VERSION 5.8 ;
BUSBITCHARS "[]" ;
DIVIDERCHAR "/" ;
UNITS
    DATABASE MICRONS 1000 ;
END UNITS

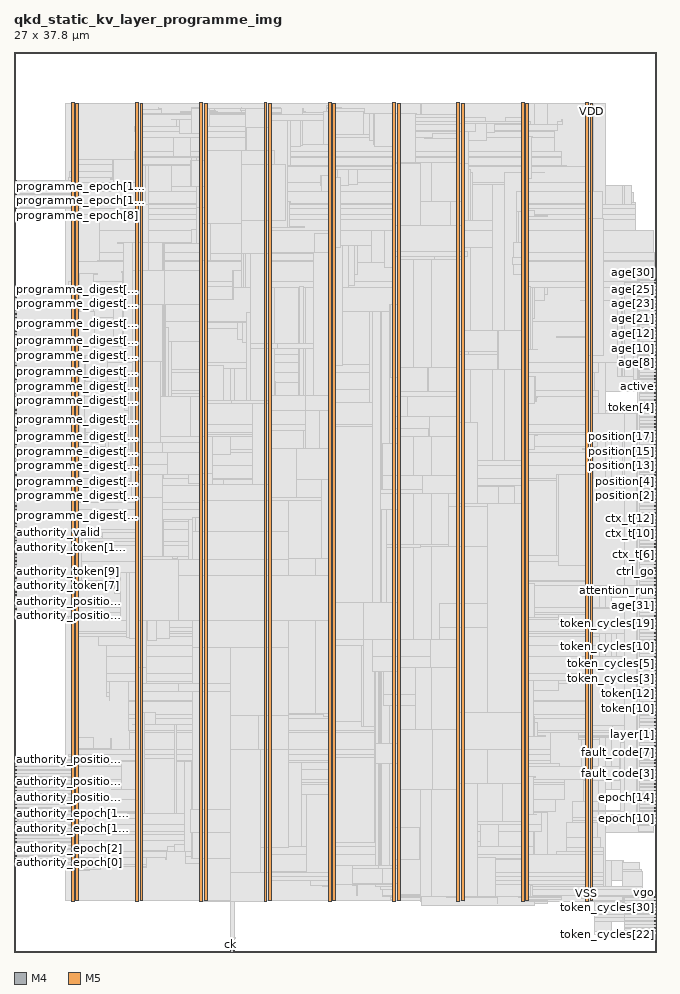
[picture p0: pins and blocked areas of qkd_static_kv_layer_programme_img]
MACRO qkd_static_kv_layer_programme_img
  FOREIGN qkd_static_kv_layer_programme_img 0 0 ;
  CLASS BLOCK ;
  SIZE 27 BY 37.8 ;
  PIN active
    DIRECTION OUTPUT ;
    USE SIGNAL ;
    PORT
      LAYER M4 ;
        RECT  26.916 23.76 27 23.784 ;
    END
  END active
  PIN age[0]
    DIRECTION OUTPUT ;
    USE SIGNAL ;
    PORT
      LAYER M4 ;
        RECT  26.916 23.904 27 23.928 ;
    END
  END age[0]
  PIN age[10]
    DIRECTION OUTPUT ;
    USE SIGNAL ;
    PORT
      LAYER M4 ;
        RECT  26.916 25.344 27 25.368 ;
    END
  END age[10]
  PIN age[11]
    DIRECTION OUTPUT ;
    USE SIGNAL ;
    PORT
      LAYER M4 ;
        RECT  26.916 25.488 27 25.512 ;
    END
  END age[11]
  PIN age[12]
    DIRECTION OUTPUT ;
    USE SIGNAL ;
    PORT
      LAYER M4 ;
        RECT  26.916 25.632 27 25.656 ;
    END
  END age[12]
  PIN age[13]
    DIRECTION OUTPUT ;
    USE SIGNAL ;
    PORT
      LAYER M4 ;
        RECT  26.916 25.776 27 25.8 ;
    END
  END age[13]
  PIN age[14]
    DIRECTION OUTPUT ;
    USE SIGNAL ;
    PORT
      LAYER M4 ;
        RECT  26.916 25.92 27 25.944 ;
    END
  END age[14]
  PIN age[15]
    DIRECTION OUTPUT ;
    USE SIGNAL ;
    PORT
      LAYER M4 ;
        RECT  26.916 26.064 27 26.088 ;
    END
  END age[15]
  PIN age[16]
    DIRECTION OUTPUT ;
    USE SIGNAL ;
    PORT
      LAYER M4 ;
        RECT  26.916 26.208 27 26.232 ;
    END
  END age[16]
  PIN age[17]
    DIRECTION OUTPUT ;
    USE SIGNAL ;
    PORT
      LAYER M4 ;
        RECT  26.916 26.352 27 26.376 ;
    END
  END age[17]
  PIN age[18]
    DIRECTION OUTPUT ;
    USE SIGNAL ;
    PORT
      LAYER M4 ;
        RECT  26.916 26.496 27 26.52 ;
    END
  END age[18]
  PIN age[19]
    DIRECTION OUTPUT ;
    USE SIGNAL ;
    PORT
      LAYER M4 ;
        RECT  26.916 26.64 27 26.664 ;
    END
  END age[19]
  PIN age[1]
    DIRECTION OUTPUT ;
    USE SIGNAL ;
    PORT
      LAYER M4 ;
        RECT  26.916 24.048 27 24.072 ;
    END
  END age[1]
  PIN age[20]
    DIRECTION OUTPUT ;
    USE SIGNAL ;
    PORT
      LAYER M4 ;
        RECT  26.916 26.784 27 26.808 ;
    END
  END age[20]
  PIN age[21]
    DIRECTION OUTPUT ;
    USE SIGNAL ;
    PORT
      LAYER M4 ;
        RECT  26.916 26.928 27 26.952 ;
    END
  END age[21]
  PIN age[22]
    DIRECTION OUTPUT ;
    USE SIGNAL ;
    PORT
      LAYER M4 ;
        RECT  26.916 27.072 27 27.096 ;
    END
  END age[22]
  PIN age[23]
    DIRECTION OUTPUT ;
    USE SIGNAL ;
    PORT
      LAYER M4 ;
        RECT  26.916 27.216 27 27.24 ;
    END
  END age[23]
  PIN age[24]
    DIRECTION OUTPUT ;
    USE SIGNAL ;
    PORT
      LAYER M4 ;
        RECT  26.916 27.36 27 27.384 ;
    END
  END age[24]
  PIN age[25]
    DIRECTION OUTPUT ;
    USE SIGNAL ;
    PORT
      LAYER M4 ;
        RECT  26.916 27.504 27 27.528 ;
    END
  END age[25]
  PIN age[26]
    DIRECTION OUTPUT ;
    USE SIGNAL ;
    PORT
      LAYER M4 ;
        RECT  26.916 27.648 27 27.672 ;
    END
  END age[26]
  PIN age[27]
    DIRECTION OUTPUT ;
    USE SIGNAL ;
    PORT
      LAYER M4 ;
        RECT  26.916 27.792 27 27.816 ;
    END
  END age[27]
  PIN age[28]
    DIRECTION OUTPUT ;
    USE SIGNAL ;
    PORT
      LAYER M4 ;
        RECT  26.916 27.936 27 27.96 ;
    END
  END age[28]
  PIN age[29]
    DIRECTION OUTPUT ;
    USE SIGNAL ;
    PORT
      LAYER M4 ;
        RECT  26.916 28.08 27 28.104 ;
    END
  END age[29]
  PIN age[2]
    DIRECTION OUTPUT ;
    USE SIGNAL ;
    PORT
      LAYER M4 ;
        RECT  26.916 24.192 27 24.216 ;
    END
  END age[2]
  PIN age[30]
    DIRECTION OUTPUT ;
    USE SIGNAL ;
    PORT
      LAYER M4 ;
        RECT  26.916 28.224 27 28.248 ;
    END
  END age[30]
  PIN age[31]
    DIRECTION OUTPUT ;
    USE SIGNAL ;
    PORT
      LAYER M4 ;
        RECT  26.916 14.544 27 14.568 ;
    END
  END age[31]
  PIN age[3]
    DIRECTION OUTPUT ;
    USE SIGNAL ;
    PORT
      LAYER M4 ;
        RECT  26.916 24.336 27 24.36 ;
    END
  END age[3]
  PIN age[4]
    DIRECTION OUTPUT ;
    USE SIGNAL ;
    PORT
      LAYER M4 ;
        RECT  26.916 24.48 27 24.504 ;
    END
  END age[4]
  PIN age[5]
    DIRECTION OUTPUT ;
    USE SIGNAL ;
    PORT
      LAYER M4 ;
        RECT  26.916 24.624 27 24.648 ;
    END
  END age[5]
  PIN age[6]
    DIRECTION OUTPUT ;
    USE SIGNAL ;
    PORT
      LAYER M4 ;
        RECT  26.916 24.768 27 24.792 ;
    END
  END age[6]
  PIN age[7]
    DIRECTION OUTPUT ;
    USE SIGNAL ;
    PORT
      LAYER M4 ;
        RECT  26.916 24.912 27 24.936 ;
    END
  END age[7]
  PIN age[8]
    DIRECTION OUTPUT ;
    USE SIGNAL ;
    PORT
      LAYER M4 ;
        RECT  26.916 25.056 27 25.08 ;
    END
  END age[8]
  PIN age[9]
    DIRECTION OUTPUT ;
    USE SIGNAL ;
    PORT
      LAYER M4 ;
        RECT  26.916 25.2 27 25.224 ;
    END
  END age[9]
  PIN attention_issue
    DIRECTION OUTPUT ;
    USE SIGNAL ;
    PORT
      LAYER M4 ;
        RECT  26.916 14.688 27 14.712 ;
    END
  END attention_issue
  PIN attention_run
    DIRECTION OUTPUT ;
    USE SIGNAL ;
    PORT
      LAYER M4 ;
        RECT  26.916 14.832 27 14.856 ;
    END
  END attention_run
  PIN authority_epoch[0]
    DIRECTION INPUT ;
    USE SIGNAL ;
    PORT
      LAYER M4 ;
        RECT  0 3.744 0.084 3.768 ;
    END
  END authority_epoch[0]
  PIN authority_epoch[10]
    DIRECTION INPUT ;
    USE SIGNAL ;
    PORT
      LAYER M4 ;
        RECT  0 5.184 0.084 5.208 ;
    END
  END authority_epoch[10]
  PIN authority_epoch[11]
    DIRECTION INPUT ;
    USE SIGNAL ;
    PORT
      LAYER M4 ;
        RECT  0 5.328 0.084 5.352 ;
    END
  END authority_epoch[11]
  PIN authority_epoch[12]
    DIRECTION INPUT ;
    USE SIGNAL ;
    PORT
      LAYER M4 ;
        RECT  0 5.472 0.084 5.496 ;
    END
  END authority_epoch[12]
  PIN authority_epoch[13]
    DIRECTION INPUT ;
    USE SIGNAL ;
    PORT
      LAYER M4 ;
        RECT  0 5.616 0.084 5.64 ;
    END
  END authority_epoch[13]
  PIN authority_epoch[14]
    DIRECTION INPUT ;
    USE SIGNAL ;
    PORT
      LAYER M4 ;
        RECT  0 5.76 0.084 5.784 ;
    END
  END authority_epoch[14]
  PIN authority_epoch[15]
    DIRECTION INPUT ;
    USE SIGNAL ;
    PORT
      LAYER M4 ;
        RECT  0 5.904 0.084 5.928 ;
    END
  END authority_epoch[15]
  PIN authority_epoch[1]
    DIRECTION INPUT ;
    USE SIGNAL ;
    PORT
      LAYER M4 ;
        RECT  0 3.888 0.084 3.912 ;
    END
  END authority_epoch[1]
  PIN authority_epoch[2]
    DIRECTION INPUT ;
    USE SIGNAL ;
    PORT
      LAYER M4 ;
        RECT  0 4.032 0.084 4.056 ;
    END
  END authority_epoch[2]
  PIN authority_epoch[3]
    DIRECTION INPUT ;
    USE SIGNAL ;
    PORT
      LAYER M4 ;
        RECT  0 4.176 0.084 4.2 ;
    END
  END authority_epoch[3]
  PIN authority_epoch[4]
    DIRECTION INPUT ;
    USE SIGNAL ;
    PORT
      LAYER M4 ;
        RECT  0 4.32 0.084 4.344 ;
    END
  END authority_epoch[4]
  PIN authority_epoch[5]
    DIRECTION INPUT ;
    USE SIGNAL ;
    PORT
      LAYER M4 ;
        RECT  0 4.464 0.084 4.488 ;
    END
  END authority_epoch[5]
  PIN authority_epoch[6]
    DIRECTION INPUT ;
    USE SIGNAL ;
    PORT
      LAYER M4 ;
        RECT  0 4.608 0.084 4.632 ;
    END
  END authority_epoch[6]
  PIN authority_epoch[7]
    DIRECTION INPUT ;
    USE SIGNAL ;
    PORT
      LAYER M4 ;
        RECT  0 4.752 0.084 4.776 ;
    END
  END authority_epoch[7]
  PIN authority_epoch[8]
    DIRECTION INPUT ;
    USE SIGNAL ;
    PORT
      LAYER M4 ;
        RECT  0 4.896 0.084 4.92 ;
    END
  END authority_epoch[8]
  PIN authority_epoch[9]
    DIRECTION INPUT ;
    USE SIGNAL ;
    PORT
      LAYER M4 ;
        RECT  0 5.04 0.084 5.064 ;
    END
  END authority_epoch[9]
  PIN authority_generation[0]
    DIRECTION INPUT ;
    USE SIGNAL ;
    PORT
      LAYER M4 ;
        RECT  0 6.048 0.084 6.072 ;
    END
  END authority_generation[0]
  PIN authority_generation[1]
    DIRECTION INPUT ;
    USE SIGNAL ;
    PORT
      LAYER M4 ;
        RECT  0 6.192 0.084 6.216 ;
    END
  END authority_generation[1]
  PIN authority_position[0]
    DIRECTION INPUT ;
    USE SIGNAL ;
    PORT
      LAYER M4 ;
        RECT  0 6.336 0.084 6.36 ;
    END
  END authority_position[0]
  PIN authority_position[10]
    DIRECTION INPUT ;
    USE SIGNAL ;
    PORT
      LAYER M4 ;
        RECT  0 7.776 0.084 7.8 ;
    END
  END authority_position[10]
  PIN authority_position[11]
    DIRECTION INPUT ;
    USE SIGNAL ;
    PORT
      LAYER M4 ;
        RECT  0 7.92 0.084 7.944 ;
    END
  END authority_position[11]
  PIN authority_position[12]
    DIRECTION INPUT ;
    USE SIGNAL ;
    PORT
      LAYER M4 ;
        RECT  0 8.064 0.084 8.088 ;
    END
  END authority_position[12]
  PIN authority_position[13]
    DIRECTION INPUT ;
    USE SIGNAL ;
    PORT
      LAYER M4 ;
        RECT  0 8.208 0.084 8.232 ;
    END
  END authority_position[13]
  PIN authority_position[14]
    DIRECTION INPUT ;
    USE SIGNAL ;
    PORT
      LAYER M4 ;
        RECT  0 14.112 0.084 14.136 ;
    END
  END authority_position[14]
  PIN authority_position[15]
    DIRECTION INPUT ;
    USE SIGNAL ;
    PORT
      LAYER M4 ;
        RECT  0 14.256 0.084 14.28 ;
    END
  END authority_position[15]
  PIN authority_position[16]
    DIRECTION INPUT ;
    USE SIGNAL ;
    PORT
      LAYER M4 ;
        RECT  0 14.4 0.084 14.424 ;
    END
  END authority_position[16]
  PIN authority_position[17]
    DIRECTION INPUT ;
    USE SIGNAL ;
    PORT
      LAYER M4 ;
        RECT  0 14.544 0.084 14.568 ;
    END
  END authority_position[17]
  PIN authority_position[1]
    DIRECTION INPUT ;
    USE SIGNAL ;
    PORT
      LAYER M4 ;
        RECT  0 6.48 0.084 6.504 ;
    END
  END authority_position[1]
  PIN authority_position[2]
    DIRECTION INPUT ;
    USE SIGNAL ;
    PORT
      LAYER M4 ;
        RECT  0 6.624 0.084 6.648 ;
    END
  END authority_position[2]
  PIN authority_position[3]
    DIRECTION INPUT ;
    USE SIGNAL ;
    PORT
      LAYER M4 ;
        RECT  0 6.768 0.084 6.792 ;
    END
  END authority_position[3]
  PIN authority_position[4]
    DIRECTION INPUT ;
    USE SIGNAL ;
    PORT
      LAYER M4 ;
        RECT  0 6.912 0.084 6.936 ;
    END
  END authority_position[4]
  PIN authority_position[5]
    DIRECTION INPUT ;
    USE SIGNAL ;
    PORT
      LAYER M4 ;
        RECT  0 7.056 0.084 7.08 ;
    END
  END authority_position[5]
  PIN authority_position[6]
    DIRECTION INPUT ;
    USE SIGNAL ;
    PORT
      LAYER M4 ;
        RECT  0 7.2 0.084 7.224 ;
    END
  END authority_position[6]
  PIN authority_position[7]
    DIRECTION INPUT ;
    USE SIGNAL ;
    PORT
      LAYER M4 ;
        RECT  0 7.344 0.084 7.368 ;
    END
  END authority_position[7]
  PIN authority_position[8]
    DIRECTION INPUT ;
    USE SIGNAL ;
    PORT
      LAYER M4 ;
        RECT  0 7.488 0.084 7.512 ;
    END
  END authority_position[8]
  PIN authority_position[9]
    DIRECTION INPUT ;
    USE SIGNAL ;
    PORT
      LAYER M4 ;
        RECT  0 7.632 0.084 7.656 ;
    END
  END authority_position[9]
  PIN authority_token[0]
    DIRECTION INPUT ;
    USE SIGNAL ;
    PORT
      LAYER M4 ;
        RECT  0 14.688 0.084 14.712 ;
    END
  END authority_token[0]
  PIN authority_token[10]
    DIRECTION INPUT ;
    USE SIGNAL ;
    PORT
      LAYER M4 ;
        RECT  0 16.128 0.084 16.152 ;
    END
  END authority_token[10]
  PIN authority_token[11]
    DIRECTION INPUT ;
    USE SIGNAL ;
    PORT
      LAYER M4 ;
        RECT  0 16.272 0.084 16.296 ;
    END
  END authority_token[11]
  PIN authority_token[12]
    DIRECTION INPUT ;
    USE SIGNAL ;
    PORT
      LAYER M4 ;
        RECT  0 16.416 0.084 16.44 ;
    END
  END authority_token[12]
  PIN authority_token[13]
    DIRECTION INPUT ;
    USE SIGNAL ;
    PORT
      LAYER M4 ;
        RECT  0 16.56 0.084 16.584 ;
    END
  END authority_token[13]
  PIN authority_token[14]
    DIRECTION INPUT ;
    USE SIGNAL ;
    PORT
      LAYER M4 ;
        RECT  0 16.704 0.084 16.728 ;
    END
  END authority_token[14]
  PIN authority_token[15]
    DIRECTION INPUT ;
    USE SIGNAL ;
    PORT
      LAYER M4 ;
        RECT  0 16.848 0.084 16.872 ;
    END
  END authority_token[15]
  PIN authority_token[16]
    DIRECTION INPUT ;
    USE SIGNAL ;
    PORT
      LAYER M4 ;
        RECT  0 16.992 0.084 17.016 ;
    END
  END authority_token[16]
  PIN authority_token[17]
    DIRECTION INPUT ;
    USE SIGNAL ;
    PORT
      LAYER M4 ;
        RECT  0 17.136 0.084 17.16 ;
    END
  END authority_token[17]
  PIN authority_token[1]
    DIRECTION INPUT ;
    USE SIGNAL ;
    PORT
      LAYER M4 ;
        RECT  0 14.832 0.084 14.856 ;
    END
  END authority_token[1]
  PIN authority_token[2]
    DIRECTION INPUT ;
    USE SIGNAL ;
    PORT
      LAYER M4 ;
        RECT  0 14.976 0.084 15 ;
    END
  END authority_token[2]
  PIN authority_token[3]
    DIRECTION INPUT ;
    USE SIGNAL ;
    PORT
      LAYER M4 ;
        RECT  0 15.12 0.084 15.144 ;
    END
  END authority_token[3]
  PIN authority_token[4]
    DIRECTION INPUT ;
    USE SIGNAL ;
    PORT
      LAYER M4 ;
        RECT  0 15.264 0.084 15.288 ;
    END
  END authority_token[4]
  PIN authority_token[5]
    DIRECTION INPUT ;
    USE SIGNAL ;
    PORT
      LAYER M4 ;
        RECT  0 15.408 0.084 15.432 ;
    END
  END authority_token[5]
  PIN authority_token[6]
    DIRECTION INPUT ;
    USE SIGNAL ;
    PORT
      LAYER M4 ;
        RECT  0 15.552 0.084 15.576 ;
    END
  END authority_token[6]
  PIN authority_token[7]
    DIRECTION INPUT ;
    USE SIGNAL ;
    PORT
      LAYER M4 ;
        RECT  0 15.696 0.084 15.72 ;
    END
  END authority_token[7]
  PIN authority_token[8]
    DIRECTION INPUT ;
    USE SIGNAL ;
    PORT
      LAYER M4 ;
        RECT  0 15.84 0.084 15.864 ;
    END
  END authority_token[8]
  PIN authority_token[9]
    DIRECTION INPUT ;
    USE SIGNAL ;
    PORT
      LAYER M4 ;
        RECT  0 15.984 0.084 16.008 ;
    END
  END authority_token[9]
  PIN authority_valid
    DIRECTION INPUT ;
    USE SIGNAL ;
    PORT
      LAYER M4 ;
        RECT  0 17.28 0.084 17.304 ;
    END
  END authority_valid
  PIN ck
    DIRECTION INPUT ;
    USE SIGNAL ;
    PORT
      LAYER M5 ;
        RECT  9.072 0 9.096 0.084 ;
    END
  END ck
  PIN completed_stage[0]
    DIRECTION OUTPUT ;
    USE SIGNAL ;
    PORT
      LAYER M4 ;
        RECT  26.916 14.976 27 15 ;
    END
  END completed_stage[0]
  PIN completed_stage[1]
    DIRECTION OUTPUT ;
    USE SIGNAL ;
    PORT
      LAYER M4 ;
        RECT  26.916 15.12 27 15.144 ;
    END
  END completed_stage[1]
  PIN completed_stage[2]
    DIRECTION OUTPUT ;
    USE SIGNAL ;
    PORT
      LAYER M4 ;
        RECT  26.916 15.264 27 15.288 ;
    END
  END completed_stage[2]
  PIN completed_stage[3]
    DIRECTION OUTPUT ;
    USE SIGNAL ;
    PORT
      LAYER M4 ;
        RECT  26.916 15.408 27 15.432 ;
    END
  END completed_stage[3]
  PIN completed_stage[4]
    DIRECTION OUTPUT ;
    USE SIGNAL ;
    PORT
      LAYER M4 ;
        RECT  26.916 15.552 27 15.576 ;
    END
  END completed_stage[4]
  PIN completed_stage[5]
    DIRECTION OUTPUT ;
    USE SIGNAL ;
    PORT
      LAYER M4 ;
        RECT  26.916 15.696 27 15.72 ;
    END
  END completed_stage[5]
  PIN configured
    DIRECTION OUTPUT ;
    USE SIGNAL ;
    PORT
      LAYER M4 ;
        RECT  26.916 15.84 27 15.864 ;
    END
  END configured
  PIN ctrl_go
    DIRECTION OUTPUT ;
    USE SIGNAL ;
    PORT
      LAYER M4 ;
        RECT  26.916 15.984 27 16.008 ;
    END
  END ctrl_go
  PIN ctx_t[0]
    DIRECTION OUTPUT ;
    USE SIGNAL ;
    PORT
      LAYER M4 ;
        RECT  26.916 16.128 27 16.152 ;
    END
  END ctx_t[0]
  PIN ctx_t[10]
    DIRECTION OUTPUT ;
    USE SIGNAL ;
    PORT
      LAYER M4 ;
        RECT  26.916 17.568 27 17.592 ;
    END
  END ctx_t[10]
  PIN ctx_t[11]
    DIRECTION OUTPUT ;
    USE SIGNAL ;
    PORT
      LAYER M4 ;
        RECT  26.916 17.712 27 17.736 ;
    END
  END ctx_t[11]
  PIN ctx_t[12]
    DIRECTION OUTPUT ;
    USE SIGNAL ;
    PORT
      LAYER M4 ;
        RECT  26.916 17.856 27 17.88 ;
    END
  END ctx_t[12]
  PIN ctx_t[13]
    DIRECTION OUTPUT ;
    USE SIGNAL ;
    PORT
      LAYER M4 ;
        RECT  26.916 18 27 18.024 ;
    END
  END ctx_t[13]
  PIN ctx_t[1]
    DIRECTION OUTPUT ;
    USE SIGNAL ;
    PORT
      LAYER M4 ;
        RECT  26.916 16.272 27 16.296 ;
    END
  END ctx_t[1]
  PIN ctx_t[2]
    DIRECTION OUTPUT ;
    USE SIGNAL ;
    PORT
      LAYER M4 ;
        RECT  26.916 16.416 27 16.44 ;
    END
  END ctx_t[2]
  PIN ctx_t[3]
    DIRECTION OUTPUT ;
    USE SIGNAL ;
    PORT
      LAYER M4 ;
        RECT  26.916 16.56 27 16.584 ;
    END
  END ctx_t[3]
  PIN ctx_t[4]
    DIRECTION OUTPUT ;
    USE SIGNAL ;
    PORT
      LAYER M4 ;
        RECT  26.916 16.704 27 16.728 ;
    END
  END ctx_t[4]
  PIN ctx_t[5]
    DIRECTION OUTPUT ;
    USE SIGNAL ;
    PORT
      LAYER M4 ;
        RECT  26.916 16.848 27 16.872 ;
    END
  END ctx_t[5]
  PIN ctx_t[6]
    DIRECTION OUTPUT ;
    USE SIGNAL ;
    PORT
      LAYER M4 ;
        RECT  26.916 16.992 27 17.016 ;
    END
  END ctx_t[6]
  PIN ctx_t[7]
    DIRECTION OUTPUT ;
    USE SIGNAL ;
    PORT
      LAYER M4 ;
        RECT  26.916 17.136 27 17.16 ;
    END
  END ctx_t[7]
  PIN ctx_t[8]
    DIRECTION OUTPUT ;
    USE SIGNAL ;
    PORT
      LAYER M4 ;
        RECT  26.916 17.28 27 17.304 ;
    END
  END ctx_t[8]
  PIN ctx_t[9]
    DIRECTION OUTPUT ;
    USE SIGNAL ;
    PORT
      LAYER M4 ;
        RECT  26.916 17.424 27 17.448 ;
    END
  END ctx_t[9]
  PIN done
    DIRECTION OUTPUT ;
    USE SIGNAL ;
    PORT
      LAYER M4 ;
        RECT  26.916 18.144 27 18.168 ;
    END
  END done
  PIN epoch[0]
    DIRECTION OUTPUT ;
    USE SIGNAL ;
    PORT
      LAYER M4 ;
        RECT  26.916 18.288 27 18.312 ;
    END
  END epoch[0]
  PIN epoch[10]
    DIRECTION OUTPUT ;
    USE SIGNAL ;
    PORT
      LAYER M4 ;
        RECT  26.916 5.904 27 5.928 ;
    END
  END epoch[10]
  PIN epoch[11]
    DIRECTION OUTPUT ;
    USE SIGNAL ;
    PORT
      LAYER M4 ;
        RECT  26.916 6.048 27 6.072 ;
    END
  END epoch[11]
  PIN epoch[12]
    DIRECTION OUTPUT ;
    USE SIGNAL ;
    PORT
      LAYER M4 ;
        RECT  26.916 6.192 27 6.216 ;
    END
  END epoch[12]
  PIN epoch[13]
    DIRECTION OUTPUT ;
    USE SIGNAL ;
    PORT
      LAYER M4 ;
        RECT  26.916 6.336 27 6.36 ;
    END
  END epoch[13]
  PIN epoch[14]
    DIRECTION OUTPUT ;
    USE SIGNAL ;
    PORT
      LAYER M4 ;
        RECT  26.916 6.48 27 6.504 ;
    END
  END epoch[14]
  PIN epoch[15]
    DIRECTION OUTPUT ;
    USE SIGNAL ;
    PORT
      LAYER M4 ;
        RECT  26.916 6.624 27 6.648 ;
    END
  END epoch[15]
  PIN epoch[1]
    DIRECTION OUTPUT ;
    USE SIGNAL ;
    PORT
      LAYER M4 ;
        RECT  26.916 18.432 27 18.456 ;
    END
  END epoch[1]
  PIN epoch[2]
    DIRECTION OUTPUT ;
    USE SIGNAL ;
    PORT
      LAYER M4 ;
        RECT  26.916 18.576 27 18.6 ;
    END
  END epoch[2]
  PIN epoch[3]
    DIRECTION OUTPUT ;
    USE SIGNAL ;
    PORT
      LAYER M4 ;
        RECT  26.916 18.72 27 18.744 ;
    END
  END epoch[3]
  PIN epoch[4]
    DIRECTION OUTPUT ;
    USE SIGNAL ;
    PORT
      LAYER M4 ;
        RECT  26.916 18.864 27 18.888 ;
    END
  END epoch[4]
  PIN epoch[5]
    DIRECTION OUTPUT ;
    USE SIGNAL ;
    PORT
      LAYER M4 ;
        RECT  26.916 19.008 27 19.032 ;
    END
  END epoch[5]
  PIN epoch[6]
    DIRECTION OUTPUT ;
    USE SIGNAL ;
    PORT
      LAYER M4 ;
        RECT  26.916 5.328 27 5.352 ;
    END
  END epoch[6]
  PIN epoch[7]
    DIRECTION OUTPUT ;
    USE SIGNAL ;
    PORT
      LAYER M4 ;
        RECT  26.916 5.472 27 5.496 ;
    END
  END epoch[7]
  PIN epoch[8]
    DIRECTION OUTPUT ;
    USE SIGNAL ;
    PORT
      LAYER M4 ;
        RECT  26.916 5.616 27 5.64 ;
    END
  END epoch[8]
  PIN epoch[9]
    DIRECTION OUTPUT ;
    USE SIGNAL ;
    PORT
      LAYER M4 ;
        RECT  26.916 5.76 27 5.784 ;
    END
  END epoch[9]
  PIN expected_upstream_quiet
    DIRECTION OUTPUT ;
    USE SIGNAL ;
    PORT
      LAYER M4 ;
        RECT  26.916 6.768 27 6.792 ;
    END
  END expected_upstream_quiet
  PIN fault
    DIRECTION OUTPUT ;
    USE SIGNAL ;
    PORT
      LAYER M4 ;
        RECT  26.916 6.912 27 6.936 ;
    END
  END fault
  PIN fault_code[0]
    DIRECTION OUTPUT ;
    USE SIGNAL ;
    PORT
      LAYER M4 ;
        RECT  26.916 7.056 27 7.08 ;
    END
  END fault_code[0]
  PIN fault_code[1]
    DIRECTION OUTPUT ;
    USE SIGNAL ;
    PORT
      LAYER M4 ;
        RECT  26.916 7.2 27 7.224 ;
    END
  END fault_code[1]
  PIN fault_code[2]
    DIRECTION OUTPUT ;
    USE SIGNAL ;
    PORT
      LAYER M4 ;
        RECT  26.916 7.344 27 7.368 ;
    END
  END fault_code[2]
  PIN fault_code[3]
    DIRECTION OUTPUT ;
    USE SIGNAL ;
    PORT
      LAYER M4 ;
        RECT  26.916 7.488 27 7.512 ;
    END
  END fault_code[3]
  PIN fault_code[4]
    DIRECTION OUTPUT ;
    USE SIGNAL ;
    PORT
      LAYER M4 ;
        RECT  26.916 7.632 27 7.656 ;
    END
  END fault_code[4]
  PIN fault_code[5]
    DIRECTION OUTPUT ;
    USE SIGNAL ;
    PORT
      LAYER M4 ;
        RECT  26.916 7.776 27 7.8 ;
    END
  END fault_code[5]
  PIN fault_code[6]
    DIRECTION OUTPUT ;
    USE SIGNAL ;
    PORT
      LAYER M4 ;
        RECT  26.916 7.92 27 7.944 ;
    END
  END fault_code[6]
  PIN fault_code[7]
    DIRECTION OUTPUT ;
    USE SIGNAL ;
    PORT
      LAYER M4 ;
        RECT  26.916 8.064 27 8.088 ;
    END
  END fault_code[7]
  PIN generation[0]
    DIRECTION OUTPUT ;
    USE SIGNAL ;
    PORT
      LAYER M4 ;
        RECT  26.916 8.208 27 8.232 ;
    END
  END generation[0]
  PIN generation[1]
    DIRECTION OUTPUT ;
    USE SIGNAL ;
    PORT
      LAYER M4 ;
        RECT  26.916 8.352 27 8.376 ;
    END
  END generation[1]
  PIN kgo
    DIRECTION OUTPUT ;
    USE SIGNAL ;
    PORT
      LAYER M4 ;
        RECT  26.916 8.496 27 8.52 ;
    END
  END kgo
  PIN layer[0]
    DIRECTION OUTPUT ;
    USE SIGNAL ;
    PORT
      LAYER M4 ;
        RECT  26.916 8.64 27 8.664 ;
    END
  END layer[0]
  PIN layer[1]
    DIRECTION OUTPUT ;
    USE SIGNAL ;
    PORT
      LAYER M4 ;
        RECT  26.916 8.784 27 8.808 ;
    END
  END layer[1]
  PIN layer[2]
    DIRECTION OUTPUT ;
    USE SIGNAL ;
    PORT
      LAYER M4 ;
        RECT  26.916 8.928 27 8.952 ;
    END
  END layer[2]
  PIN layer[3]
    DIRECTION OUTPUT ;
    USE SIGNAL ;
    PORT
      LAYER M4 ;
        RECT  26.916 9.072 27 9.096 ;
    END
  END layer[3]
  PIN layer[4]
    DIRECTION OUTPUT ;
    USE SIGNAL ;
    PORT
      LAYER M4 ;
        RECT  26.916 9.216 27 9.24 ;
    END
  END layer[4]
  PIN layer[5]
    DIRECTION OUTPUT ;
    USE SIGNAL ;
    PORT
      LAYER M4 ;
        RECT  26.916 9.36 27 9.384 ;
    END
  END layer[5]
  PIN link_start
    DIRECTION OUTPUT ;
    USE SIGNAL ;
    PORT
      LAYER M4 ;
        RECT  26.916 9.504 27 9.528 ;
    END
  END link_start
  PIN position[0]
    DIRECTION OUTPUT ;
    USE SIGNAL ;
    PORT
      LAYER M4 ;
        RECT  26.916 9.648 27 9.672 ;
    END
  END position[0]
  PIN position[10]
    DIRECTION OUTPUT ;
    USE SIGNAL ;
    PORT
      LAYER M4 ;
        RECT  26.916 20.304 27 20.328 ;
    END
  END position[10]
  PIN position[11]
    DIRECTION OUTPUT ;
    USE SIGNAL ;
    PORT
      LAYER M4 ;
        RECT  26.916 20.448 27 20.472 ;
    END
  END position[11]
  PIN position[12]
    DIRECTION OUTPUT ;
    USE SIGNAL ;
    PORT
      LAYER M4 ;
        RECT  26.916 20.592 27 20.616 ;
    END
  END position[12]
  PIN position[13]
    DIRECTION OUTPUT ;
    USE SIGNAL ;
    PORT
      LAYER M4 ;
        RECT  26.916 20.736 27 20.76 ;
    END
  END position[13]
  PIN position[14]
    DIRECTION OUTPUT ;
    USE SIGNAL ;
    PORT
      LAYER M4 ;
        RECT  26.916 20.88 27 20.904 ;
    END
  END position[14]
  PIN position[15]
    DIRECTION OUTPUT ;
    USE SIGNAL ;
    PORT
      LAYER M4 ;
        RECT  26.916 21.024 27 21.048 ;
    END
  END position[15]
  PIN position[16]
    DIRECTION OUTPUT ;
    USE SIGNAL ;
    PORT
      LAYER M4 ;
        RECT  26.916 21.168 27 21.192 ;
    END
  END position[16]
  PIN position[17]
    DIRECTION OUTPUT ;
    USE SIGNAL ;
    PORT
      LAYER M4 ;
        RECT  26.916 21.312 27 21.336 ;
    END
  END position[17]
  PIN position[1]
    DIRECTION OUTPUT ;
    USE SIGNAL ;
    PORT
      LAYER M4 ;
        RECT  26.916 9.792 27 9.816 ;
    END
  END position[1]
  PIN position[2]
    DIRECTION OUTPUT ;
    USE SIGNAL ;
    PORT
      LAYER M4 ;
        RECT  26.916 19.152 27 19.176 ;
    END
  END position[2]
  PIN position[3]
    DIRECTION OUTPUT ;
    USE SIGNAL ;
    PORT
      LAYER M4 ;
        RECT  26.916 19.296 27 19.32 ;
    END
  END position[3]
  PIN position[4]
    DIRECTION OUTPUT ;
    USE SIGNAL ;
    PORT
      LAYER M4 ;
        RECT  26.916 19.44 27 19.464 ;
    END
  END position[4]
  PIN position[5]
    DIRECTION OUTPUT ;
    USE SIGNAL ;
    PORT
      LAYER M4 ;
        RECT  26.916 19.584 27 19.608 ;
    END
  END position[5]
  PIN position[6]
    DIRECTION OUTPUT ;
    USE SIGNAL ;
    PORT
      LAYER M4 ;
        RECT  26.916 19.728 27 19.752 ;
    END
  END position[6]
  PIN position[7]
    DIRECTION OUTPUT ;
    USE SIGNAL ;
    PORT
      LAYER M4 ;
        RECT  26.916 19.872 27 19.896 ;
    END
  END position[7]
  PIN position[8]
    DIRECTION OUTPUT ;
    USE SIGNAL ;
    PORT
      LAYER M4 ;
        RECT  26.916 20.016 27 20.04 ;
    END
  END position[8]
  PIN position[9]
    DIRECTION OUTPUT ;
    USE SIGNAL ;
    PORT
      LAYER M4 ;
        RECT  26.916 20.16 27 20.184 ;
    END
  END position[9]
  PIN programme_authorized
    DIRECTION INPUT ;
    USE SIGNAL ;
    PORT
      LAYER M4 ;
        RECT  0 17.424 0.084 17.448 ;
    END
  END programme_authorized
  PIN programme_digest[0]
    DIRECTION INPUT ;
    USE SIGNAL ;
    PORT
      LAYER M4 ;
        RECT  0 17.568 0.084 17.592 ;
    END
  END programme_digest[0]
  PIN programme_digest[10]
    DIRECTION INPUT ;
    USE SIGNAL ;
    PORT
      LAYER M4 ;
        RECT  0 23.616 0.084 23.64 ;
    END
  END programme_digest[10]
  PIN programme_digest[11]
    DIRECTION INPUT ;
    USE SIGNAL ;
    PORT
      LAYER M4 ;
        RECT  0 23.76 0.084 23.784 ;
    END
  END programme_digest[11]
  PIN programme_digest[12]
    DIRECTION INPUT ;
    USE SIGNAL ;
    PORT
      LAYER M4 ;
        RECT  0 23.904 0.084 23.928 ;
    END
  END programme_digest[12]
  PIN programme_digest[13]
    DIRECTION INPUT ;
    USE SIGNAL ;
    PORT
      LAYER M4 ;
        RECT  0 24.048 0.084 24.072 ;
    END
  END programme_digest[13]
  PIN programme_digest[14]
    DIRECTION INPUT ;
    USE SIGNAL ;
    PORT
      LAYER M4 ;
        RECT  0 24.192 0.084 24.216 ;
    END
  END programme_digest[14]
  PIN programme_digest[15]
    DIRECTION INPUT ;
    USE SIGNAL ;
    PORT
      LAYER M4 ;
        RECT  0 24.336 0.084 24.36 ;
    END
  END programme_digest[15]
  PIN programme_digest[16]
    DIRECTION INPUT ;
    USE SIGNAL ;
    PORT
      LAYER M4 ;
        RECT  0 24.48 0.084 24.504 ;
    END
  END programme_digest[16]
  PIN programme_digest[17]
    DIRECTION INPUT ;
    USE SIGNAL ;
    PORT
      LAYER M4 ;
        RECT  0 24.624 0.084 24.648 ;
    END
  END programme_digest[17]
  PIN programme_digest[18]
    DIRECTION INPUT ;
    USE SIGNAL ;
    PORT
      LAYER M4 ;
        RECT  0 24.768 0.084 24.792 ;
    END
  END programme_digest[18]
  PIN programme_digest[19]
    DIRECTION INPUT ;
    USE SIGNAL ;
    PORT
      LAYER M4 ;
        RECT  0 24.912 0.084 24.936 ;
    END
  END programme_digest[19]
  PIN programme_digest[1]
    DIRECTION INPUT ;
    USE SIGNAL ;
    PORT
      LAYER M4 ;
        RECT  0 17.712 0.084 17.736 ;
    END
  END programme_digest[1]
  PIN programme_digest[20]
    DIRECTION INPUT ;
    USE SIGNAL ;
    PORT
      LAYER M4 ;
        RECT  0 25.056 0.084 25.08 ;
    END
  END programme_digest[20]
  PIN programme_digest[21]
    DIRECTION INPUT ;
    USE SIGNAL ;
    PORT
      LAYER M4 ;
        RECT  0 25.2 0.084 25.224 ;
    END
  END programme_digest[21]
  PIN programme_digest[22]
    DIRECTION INPUT ;
    USE SIGNAL ;
    PORT
      LAYER M4 ;
        RECT  0 25.344 0.084 25.368 ;
    END
  END programme_digest[22]
  PIN programme_digest[23]
    DIRECTION INPUT ;
    USE SIGNAL ;
    PORT
      LAYER M4 ;
        RECT  0 25.488 0.084 25.512 ;
    END
  END programme_digest[23]
  PIN programme_digest[24]
    DIRECTION INPUT ;
    USE SIGNAL ;
    PORT
      LAYER M4 ;
        RECT  0 25.632 0.084 25.656 ;
    END
  END programme_digest[24]
  PIN programme_digest[25]
    DIRECTION INPUT ;
    USE SIGNAL ;
    PORT
      LAYER M4 ;
        RECT  0 25.776 0.084 25.8 ;
    END
  END programme_digest[25]
  PIN programme_digest[26]
    DIRECTION INPUT ;
    USE SIGNAL ;
    PORT
      LAYER M4 ;
        RECT  0 25.92 0.084 25.944 ;
    END
  END programme_digest[26]
  PIN programme_digest[27]
    DIRECTION INPUT ;
    USE SIGNAL ;
    PORT
      LAYER M4 ;
        RECT  0 26.064 0.084 26.088 ;
    END
  END programme_digest[27]
  PIN programme_digest[28]
    DIRECTION INPUT ;
    USE SIGNAL ;
    PORT
      LAYER M4 ;
        RECT  0 26.208 0.084 26.232 ;
    END
  END programme_digest[28]
  PIN programme_digest[29]
    DIRECTION INPUT ;
    USE SIGNAL ;
    PORT
      LAYER M4 ;
        RECT  0 26.352 0.084 26.376 ;
    END
  END programme_digest[29]
  PIN programme_digest[2]
    DIRECTION INPUT ;
    USE SIGNAL ;
    PORT
      LAYER M4 ;
        RECT  0 17.856 0.084 17.88 ;
    END
  END programme_digest[2]
  PIN programme_digest[30]
    DIRECTION INPUT ;
    USE SIGNAL ;
    PORT
      LAYER M4 ;
        RECT  0 26.496 0.084 26.52 ;
    END
  END programme_digest[30]
  PIN programme_digest[31]
    DIRECTION INPUT ;
    USE SIGNAL ;
    PORT
      LAYER M4 ;
        RECT  0 26.64 0.084 26.664 ;
    END
  END programme_digest[31]
  PIN programme_digest[32]
    DIRECTION INPUT ;
    USE SIGNAL ;
    PORT
      LAYER M4 ;
        RECT  0 26.784 0.084 26.808 ;
    END
  END programme_digest[32]
  PIN programme_digest[33]
    DIRECTION INPUT ;
    USE SIGNAL ;
    PORT
      LAYER M4 ;
        RECT  0 26.928 0.084 26.952 ;
    END
  END programme_digest[33]
  PIN programme_digest[34]
    DIRECTION INPUT ;
    USE SIGNAL ;
    PORT
      LAYER M4 ;
        RECT  0 27.072 0.084 27.096 ;
    END
  END programme_digest[34]
  PIN programme_digest[35]
    DIRECTION INPUT ;
    USE SIGNAL ;
    PORT
      LAYER M4 ;
        RECT  0 27.216 0.084 27.24 ;
    END
  END programme_digest[35]
  PIN programme_digest[36]
    DIRECTION INPUT ;
    USE SIGNAL ;
    PORT
      LAYER M4 ;
        RECT  0 27.36 0.084 27.384 ;
    END
  END programme_digest[36]
  PIN programme_digest[37]
    DIRECTION INPUT ;
    USE SIGNAL ;
    PORT
      LAYER M4 ;
        RECT  0 27.504 0.084 27.528 ;
    END
  END programme_digest[37]
  PIN programme_digest[38]
    DIRECTION INPUT ;
    USE SIGNAL ;
    PORT
      LAYER M4 ;
        RECT  0 27.648 0.084 27.672 ;
    END
  END programme_digest[38]
  PIN programme_digest[39]
    DIRECTION INPUT ;
    USE SIGNAL ;
    PORT
      LAYER M4 ;
        RECT  0 27.792 0.084 27.816 ;
    END
  END programme_digest[39]
  PIN programme_digest[3]
    DIRECTION INPUT ;
    USE SIGNAL ;
    PORT
      LAYER M4 ;
        RECT  0 18 0.084 18.024 ;
    END
  END programme_digest[3]
  PIN programme_digest[40]
    DIRECTION INPUT ;
    USE SIGNAL ;
    PORT
      LAYER M4 ;
        RECT  0 18.72 0.084 18.744 ;
    END
  END programme_digest[40]
  PIN programme_digest[41]
    DIRECTION INPUT ;
    USE SIGNAL ;
    PORT
      LAYER M4 ;
        RECT  0 18.864 0.084 18.888 ;
    END
  END programme_digest[41]
  PIN programme_digest[42]
    DIRECTION INPUT ;
    USE SIGNAL ;
    PORT
      LAYER M4 ;
        RECT  0 19.008 0.084 19.032 ;
    END
  END programme_digest[42]
  PIN programme_digest[43]
    DIRECTION INPUT ;
    USE SIGNAL ;
    PORT
      LAYER M4 ;
        RECT  0 19.152 0.084 19.176 ;
    END
  END programme_digest[43]
  PIN programme_digest[44]
    DIRECTION INPUT ;
    USE SIGNAL ;
    PORT
      LAYER M4 ;
        RECT  0 19.296 0.084 19.32 ;
    END
  END programme_digest[44]
  PIN programme_digest[45]
    DIRECTION INPUT ;
    USE SIGNAL ;
    PORT
      LAYER M4 ;
        RECT  0 19.44 0.084 19.464 ;
    END
  END programme_digest[45]
  PIN programme_digest[46]
    DIRECTION INPUT ;
    USE SIGNAL ;
    PORT
      LAYER M4 ;
        RECT  0 19.584 0.084 19.608 ;
    END
  END programme_digest[46]
  PIN programme_digest[47]
    DIRECTION INPUT ;
    USE SIGNAL ;
    PORT
      LAYER M4 ;
        RECT  0 19.728 0.084 19.752 ;
    END
  END programme_digest[47]
  PIN programme_digest[48]
    DIRECTION INPUT ;
    USE SIGNAL ;
    PORT
      LAYER M4 ;
        RECT  0 19.872 0.084 19.896 ;
    END
  END programme_digest[48]
  PIN programme_digest[49]
    DIRECTION INPUT ;
    USE SIGNAL ;
    PORT
      LAYER M4 ;
        RECT  0 20.016 0.084 20.04 ;
    END
  END programme_digest[49]
  PIN programme_digest[4]
    DIRECTION INPUT ;
    USE SIGNAL ;
    PORT
      LAYER M4 ;
        RECT  0 18.144 0.084 18.168 ;
    END
  END programme_digest[4]
  PIN programme_digest[50]
    DIRECTION INPUT ;
    USE SIGNAL ;
    PORT
      LAYER M4 ;
        RECT  0 20.16 0.084 20.184 ;
    END
  END programme_digest[50]
  PIN programme_digest[51]
    DIRECTION INPUT ;
    USE SIGNAL ;
    PORT
      LAYER M4 ;
        RECT  0 20.304 0.084 20.328 ;
    END
  END programme_digest[51]
  PIN programme_digest[52]
    DIRECTION INPUT ;
    USE SIGNAL ;
    PORT
      LAYER M4 ;
        RECT  0 20.448 0.084 20.472 ;
    END
  END programme_digest[52]
  PIN programme_digest[53]
    DIRECTION INPUT ;
    USE SIGNAL ;
    PORT
      LAYER M4 ;
        RECT  0 20.592 0.084 20.616 ;
    END
  END programme_digest[53]
  PIN programme_digest[54]
    DIRECTION INPUT ;
    USE SIGNAL ;
    PORT
      LAYER M4 ;
        RECT  0 20.736 0.084 20.76 ;
    END
  END programme_digest[54]
  PIN programme_digest[55]
    DIRECTION INPUT ;
    USE SIGNAL ;
    PORT
      LAYER M4 ;
        RECT  0 20.88 0.084 20.904 ;
    END
  END programme_digest[55]
  PIN programme_digest[56]
    DIRECTION INPUT ;
    USE SIGNAL ;
    PORT
      LAYER M4 ;
        RECT  0 21.024 0.084 21.048 ;
    END
  END programme_digest[56]
  PIN programme_digest[57]
    DIRECTION INPUT ;
    USE SIGNAL ;
    PORT
      LAYER M4 ;
        RECT  0 21.168 0.084 21.192 ;
    END
  END programme_digest[57]
  PIN programme_digest[58]
    DIRECTION INPUT ;
    USE SIGNAL ;
    PORT
      LAYER M4 ;
        RECT  0 21.312 0.084 21.336 ;
    END
  END programme_digest[58]
  PIN programme_digest[59]
    DIRECTION INPUT ;
    USE SIGNAL ;
    PORT
      LAYER M4 ;
        RECT  0 21.456 0.084 21.48 ;
    END
  END programme_digest[59]
  PIN programme_digest[5]
    DIRECTION INPUT ;
    USE SIGNAL ;
    PORT
      LAYER M4 ;
        RECT  0 18.288 0.084 18.312 ;
    END
  END programme_digest[5]
  PIN programme_digest[60]
    DIRECTION INPUT ;
    USE SIGNAL ;
    PORT
      LAYER M4 ;
        RECT  0 21.6 0.084 21.624 ;
    END
  END programme_digest[60]
  PIN programme_digest[61]
    DIRECTION INPUT ;
    USE SIGNAL ;
    PORT
      LAYER M4 ;
        RECT  0 21.744 0.084 21.768 ;
    END
  END programme_digest[61]
  PIN programme_digest[62]
    DIRECTION INPUT ;
    USE SIGNAL ;
    PORT
      LAYER M4 ;
        RECT  0 21.888 0.084 21.912 ;
    END
  END programme_digest[62]
  PIN programme_digest[63]
    DIRECTION INPUT ;
    USE SIGNAL ;
    PORT
      LAYER M4 ;
        RECT  0 22.032 0.084 22.056 ;
    END
  END programme_digest[63]
  PIN programme_digest[6]
    DIRECTION INPUT ;
    USE SIGNAL ;
    PORT
      LAYER M4 ;
        RECT  0 18.432 0.084 18.456 ;
    END
  END programme_digest[6]
  PIN programme_digest[7]
    DIRECTION INPUT ;
    USE SIGNAL ;
    PORT
      LAYER M4 ;
        RECT  0 18.576 0.084 18.6 ;
    END
  END programme_digest[7]
  PIN programme_digest[8]
    DIRECTION INPUT ;
    USE SIGNAL ;
    PORT
      LAYER M4 ;
        RECT  0 23.328 0.084 23.352 ;
    END
  END programme_digest[8]
  PIN programme_digest[9]
    DIRECTION INPUT ;
    USE SIGNAL ;
    PORT
      LAYER M4 ;
        RECT  0 23.472 0.084 23.496 ;
    END
  END programme_digest[9]
  PIN programme_epoch[0]
    DIRECTION INPUT ;
    USE SIGNAL ;
    PORT
      LAYER M4 ;
        RECT  0 22.176 0.084 22.2 ;
    END
  END programme_epoch[0]
  PIN programme_epoch[10]
    DIRECTION INPUT ;
    USE SIGNAL ;
    PORT
      LAYER M4 ;
        RECT  0 31.536 0.084 31.56 ;
    END
  END programme_epoch[10]
  PIN programme_epoch[11]
    DIRECTION INPUT ;
    USE SIGNAL ;
    PORT
      LAYER M4 ;
        RECT  0 31.68 0.084 31.704 ;
    END
  END programme_epoch[11]
  PIN programme_epoch[12]
    DIRECTION INPUT ;
    USE SIGNAL ;
    PORT
      LAYER M4 ;
        RECT  0 31.824 0.084 31.848 ;
    END
  END programme_epoch[12]
  PIN programme_epoch[13]
    DIRECTION INPUT ;
    USE SIGNAL ;
    PORT
      LAYER M4 ;
        RECT  0 31.968 0.084 31.992 ;
    END
  END programme_epoch[13]
  PIN programme_epoch[14]
    DIRECTION INPUT ;
    USE SIGNAL ;
    PORT
      LAYER M4 ;
        RECT  0 32.112 0.084 32.136 ;
    END
  END programme_epoch[14]
  PIN programme_epoch[15]
    DIRECTION INPUT ;
    USE SIGNAL ;
    PORT
      LAYER M4 ;
        RECT  0 32.256 0.084 32.28 ;
    END
  END programme_epoch[15]
  PIN programme_epoch[1]
    DIRECTION INPUT ;
    USE SIGNAL ;
    PORT
      LAYER M4 ;
        RECT  0 22.32 0.084 22.344 ;
    END
  END programme_epoch[1]
  PIN programme_epoch[2]
    DIRECTION INPUT ;
    USE SIGNAL ;
    PORT
      LAYER M4 ;
        RECT  0 22.464 0.084 22.488 ;
    END
  END programme_epoch[2]
  PIN programme_epoch[3]
    DIRECTION INPUT ;
    USE SIGNAL ;
    PORT
      LAYER M4 ;
        RECT  0 22.608 0.084 22.632 ;
    END
  END programme_epoch[3]
  PIN programme_epoch[4]
    DIRECTION INPUT ;
    USE SIGNAL ;
    PORT
      LAYER M4 ;
        RECT  0 22.752 0.084 22.776 ;
    END
  END programme_epoch[4]
  PIN programme_epoch[5]
    DIRECTION INPUT ;
    USE SIGNAL ;
    PORT
      LAYER M4 ;
        RECT  0 22.896 0.084 22.92 ;
    END
  END programme_epoch[5]
  PIN programme_epoch[6]
    DIRECTION INPUT ;
    USE SIGNAL ;
    PORT
      LAYER M4 ;
        RECT  0 23.04 0.084 23.064 ;
    END
  END programme_epoch[6]
  PIN programme_epoch[7]
    DIRECTION INPUT ;
    USE SIGNAL ;
    PORT
      LAYER M4 ;
        RECT  0 23.184 0.084 23.208 ;
    END
  END programme_epoch[7]
  PIN programme_epoch[8]
    DIRECTION INPUT ;
    USE SIGNAL ;
    PORT
      LAYER M4 ;
        RECT  0 31.248 0.084 31.272 ;
    END
  END programme_epoch[8]
  PIN programme_epoch[9]
    DIRECTION INPUT ;
    USE SIGNAL ;
    PORT
      LAYER M4 ;
        RECT  0 31.392 0.084 31.416 ;
    END
  END programme_epoch[9]
  PIN rst_n
    DIRECTION INPUT ;
    USE SIGNAL ;
    PORT
      LAYER M5 ;
        RECT  9.216 0 9.24 0.084 ;
    END
  END rst_n
  PIN stage[0]
    DIRECTION OUTPUT ;
    USE SIGNAL ;
    PORT
      LAYER M4 ;
        RECT  26.916 21.456 27 21.48 ;
    END
  END stage[0]
  PIN stage[1]
    DIRECTION OUTPUT ;
    USE SIGNAL ;
    PORT
      LAYER M4 ;
        RECT  26.916 21.6 27 21.624 ;
    END
  END stage[1]
  PIN stage[2]
    DIRECTION OUTPUT ;
    USE SIGNAL ;
    PORT
      LAYER M4 ;
        RECT  26.916 21.744 27 21.768 ;
    END
  END stage[2]
  PIN stage[3]
    DIRECTION OUTPUT ;
    USE SIGNAL ;
    PORT
      LAYER M4 ;
        RECT  26.916 21.888 27 21.912 ;
    END
  END stage[3]
  PIN stage[4]
    DIRECTION OUTPUT ;
    USE SIGNAL ;
    PORT
      LAYER M4 ;
        RECT  26.916 22.032 27 22.056 ;
    END
  END stage[4]
  PIN stage[5]
    DIRECTION OUTPUT ;
    USE SIGNAL ;
    PORT
      LAYER M4 ;
        RECT  26.916 22.176 27 22.2 ;
    END
  END stage[5]
  PIN stage_done
    DIRECTION OUTPUT ;
    USE SIGNAL ;
    PORT
      LAYER M4 ;
        RECT  26.916 22.32 27 22.344 ;
    END
  END stage_done
  PIN stage_start
    DIRECTION OUTPUT ;
    USE SIGNAL ;
    PORT
      LAYER M4 ;
        RECT  26.916 22.464 27 22.488 ;
    END
  END stage_start
  PIN start
    DIRECTION INPUT ;
    USE SIGNAL ;
    PORT
      LAYER M4 ;
        RECT  0 32.4 0.084 32.424 ;
    END
  END start
  PIN token[0]
    DIRECTION OUTPUT ;
    USE SIGNAL ;
    PORT
      LAYER M4 ;
        RECT  26.916 22.608 27 22.632 ;
    END
  END token[0]
  PIN token[10]
    DIRECTION OUTPUT ;
    USE SIGNAL ;
    PORT
      LAYER M4 ;
        RECT  26.916 10.224 27 10.248 ;
    END
  END token[10]
  PIN token[11]
    DIRECTION OUTPUT ;
    USE SIGNAL ;
    PORT
      LAYER M4 ;
        RECT  26.916 10.368 27 10.392 ;
    END
  END token[11]
  PIN token[12]
    DIRECTION OUTPUT ;
    USE SIGNAL ;
    PORT
      LAYER M4 ;
        RECT  26.916 10.512 27 10.536 ;
    END
  END token[12]
  PIN token[13]
    DIRECTION OUTPUT ;
    USE SIGNAL ;
    PORT
      LAYER M4 ;
        RECT  26.916 10.656 27 10.68 ;
    END
  END token[13]
  PIN token[14]
    DIRECTION OUTPUT ;
    USE SIGNAL ;
    PORT
      LAYER M4 ;
        RECT  26.916 10.8 27 10.824 ;
    END
  END token[14]
  PIN token[15]
    DIRECTION OUTPUT ;
    USE SIGNAL ;
    PORT
      LAYER M4 ;
        RECT  26.916 10.944 27 10.968 ;
    END
  END token[15]
  PIN token[16]
    DIRECTION OUTPUT ;
    USE SIGNAL ;
    PORT
      LAYER M4 ;
        RECT  26.916 11.088 27 11.112 ;
    END
  END token[16]
  PIN token[17]
    DIRECTION OUTPUT ;
    USE SIGNAL ;
    PORT
      LAYER M4 ;
        RECT  26.916 11.232 27 11.256 ;
    END
  END token[17]
  PIN token[1]
    DIRECTION OUTPUT ;
    USE SIGNAL ;
    PORT
      LAYER M4 ;
        RECT  26.916 22.752 27 22.776 ;
    END
  END token[1]
  PIN token[2]
    DIRECTION OUTPUT ;
    USE SIGNAL ;
    PORT
      LAYER M4 ;
        RECT  26.916 22.896 27 22.92 ;
    END
  END token[2]
  PIN token[3]
    DIRECTION OUTPUT ;
    USE SIGNAL ;
    PORT
      LAYER M4 ;
        RECT  26.916 23.04 27 23.064 ;
    END
  END token[3]
  PIN token[4]
    DIRECTION OUTPUT ;
    USE SIGNAL ;
    PORT
      LAYER M4 ;
        RECT  26.916 23.184 27 23.208 ;
    END
  END token[4]
  PIN token[5]
    DIRECTION OUTPUT ;
    USE SIGNAL ;
    PORT
      LAYER M4 ;
        RECT  26.916 23.328 27 23.352 ;
    END
  END token[5]
  PIN token[6]
    DIRECTION OUTPUT ;
    USE SIGNAL ;
    PORT
      LAYER M4 ;
        RECT  26.916 23.472 27 23.496 ;
    END
  END token[6]
  PIN token[7]
    DIRECTION OUTPUT ;
    USE SIGNAL ;
    PORT
      LAYER M4 ;
        RECT  26.916 23.616 27 23.64 ;
    END
  END token[7]
  PIN token[8]
    DIRECTION OUTPUT ;
    USE SIGNAL ;
    PORT
      LAYER M4 ;
        RECT  26.916 9.936 27 9.96 ;
    END
  END token[8]
  PIN token[9]
    DIRECTION OUTPUT ;
    USE SIGNAL ;
    PORT
      LAYER M4 ;
        RECT  26.916 10.08 27 10.104 ;
    END
  END token[9]
  PIN token_cycles[0]
    DIRECTION OUTPUT ;
    USE SIGNAL ;
    PORT
      LAYER M4 ;
        RECT  26.916 11.376 27 11.4 ;
    END
  END token_cycles[0]
  PIN token_cycles[10]
    DIRECTION OUTPUT ;
    USE SIGNAL ;
    PORT
      LAYER M4 ;
        RECT  26.916 12.816 27 12.84 ;
    END
  END token_cycles[10]
  PIN token_cycles[11]
    DIRECTION OUTPUT ;
    USE SIGNAL ;
    PORT
      LAYER M4 ;
        RECT  26.916 12.96 27 12.984 ;
    END
  END token_cycles[11]
  PIN token_cycles[12]
    DIRECTION OUTPUT ;
    USE SIGNAL ;
    PORT
      LAYER M4 ;
        RECT  26.916 13.104 27 13.128 ;
    END
  END token_cycles[12]
  PIN token_cycles[13]
    DIRECTION OUTPUT ;
    USE SIGNAL ;
    PORT
      LAYER M4 ;
        RECT  26.916 13.248 27 13.272 ;
    END
  END token_cycles[13]
  PIN token_cycles[14]
    DIRECTION OUTPUT ;
    USE SIGNAL ;
    PORT
      LAYER M4 ;
        RECT  26.916 13.392 27 13.416 ;
    END
  END token_cycles[14]
  PIN token_cycles[15]
    DIRECTION OUTPUT ;
    USE SIGNAL ;
    PORT
      LAYER M4 ;
        RECT  26.916 13.536 27 13.56 ;
    END
  END token_cycles[15]
  PIN token_cycles[16]
    DIRECTION OUTPUT ;
    USE SIGNAL ;
    PORT
      LAYER M4 ;
        RECT  26.916 13.68 27 13.704 ;
    END
  END token_cycles[16]
  PIN token_cycles[17]
    DIRECTION OUTPUT ;
    USE SIGNAL ;
    PORT
      LAYER M4 ;
        RECT  26.916 13.824 27 13.848 ;
    END
  END token_cycles[17]
  PIN token_cycles[18]
    DIRECTION OUTPUT ;
    USE SIGNAL ;
    PORT
      LAYER M4 ;
        RECT  26.916 13.968 27 13.992 ;
    END
  END token_cycles[18]
  PIN token_cycles[19]
    DIRECTION OUTPUT ;
    USE SIGNAL ;
    PORT
      LAYER M4 ;
        RECT  26.916 14.112 27 14.136 ;
    END
  END token_cycles[19]
  PIN token_cycles[1]
    DIRECTION OUTPUT ;
    USE SIGNAL ;
    PORT
      LAYER M4 ;
        RECT  26.916 11.52 27 11.544 ;
    END
  END token_cycles[1]
  PIN token_cycles[20]
    DIRECTION OUTPUT ;
    USE SIGNAL ;
    PORT
      LAYER M4 ;
        RECT  26.916 14.256 27 14.28 ;
    END
  END token_cycles[20]
  PIN token_cycles[21]
    DIRECTION OUTPUT ;
    USE SIGNAL ;
    PORT
      LAYER M4 ;
        RECT  26.916 14.4 27 14.424 ;
    END
  END token_cycles[21]
  PIN token_cycles[22]
    DIRECTION OUTPUT ;
    USE SIGNAL ;
    PORT
      LAYER M4 ;
        RECT  26.916 0.72 27 0.744 ;
    END
  END token_cycles[22]
  PIN token_cycles[23]
    DIRECTION OUTPUT ;
    USE SIGNAL ;
    PORT
      LAYER M4 ;
        RECT  26.916 0.864 27 0.888 ;
    END
  END token_cycles[23]
  PIN token_cycles[24]
    DIRECTION OUTPUT ;
    USE SIGNAL ;
    PORT
      LAYER M4 ;
        RECT  26.916 1.008 27 1.032 ;
    END
  END token_cycles[24]
  PIN token_cycles[25]
    DIRECTION OUTPUT ;
    USE SIGNAL ;
    PORT
      LAYER M4 ;
        RECT  26.916 1.152 27 1.176 ;
    END
  END token_cycles[25]
  PIN token_cycles[26]
    DIRECTION OUTPUT ;
    USE SIGNAL ;
    PORT
      LAYER M4 ;
        RECT  26.916 1.296 27 1.32 ;
    END
  END token_cycles[26]
  PIN token_cycles[27]
    DIRECTION OUTPUT ;
    USE SIGNAL ;
    PORT
      LAYER M4 ;
        RECT  26.916 1.44 27 1.464 ;
    END
  END token_cycles[27]
  PIN token_cycles[28]
    DIRECTION OUTPUT ;
    USE SIGNAL ;
    PORT
      LAYER M4 ;
        RECT  26.916 1.584 27 1.608 ;
    END
  END token_cycles[28]
  PIN token_cycles[29]
    DIRECTION OUTPUT ;
    USE SIGNAL ;
    PORT
      LAYER M4 ;
        RECT  26.916 1.728 27 1.752 ;
    END
  END token_cycles[29]
  PIN token_cycles[2]
    DIRECTION OUTPUT ;
    USE SIGNAL ;
    PORT
      LAYER M4 ;
        RECT  26.916 11.664 27 11.688 ;
    END
  END token_cycles[2]
  PIN token_cycles[30]
    DIRECTION OUTPUT ;
    USE SIGNAL ;
    PORT
      LAYER M4 ;
        RECT  26.916 1.872 27 1.896 ;
    END
  END token_cycles[30]
  PIN token_cycles[31]
    DIRECTION OUTPUT ;
    USE SIGNAL ;
    PORT
      LAYER M4 ;
        RECT  26.916 2.016 27 2.04 ;
    END
  END token_cycles[31]
  PIN token_cycles[3]
    DIRECTION OUTPUT ;
    USE SIGNAL ;
    PORT
      LAYER M4 ;
        RECT  26.916 11.808 27 11.832 ;
    END
  END token_cycles[3]
  PIN token_cycles[4]
    DIRECTION OUTPUT ;
    USE SIGNAL ;
    PORT
      LAYER M4 ;
        RECT  26.916 11.952 27 11.976 ;
    END
  END token_cycles[4]
  PIN token_cycles[5]
    DIRECTION OUTPUT ;
    USE SIGNAL ;
    PORT
      LAYER M4 ;
        RECT  26.916 12.096 27 12.12 ;
    END
  END token_cycles[5]
  PIN token_cycles[6]
    DIRECTION OUTPUT ;
    USE SIGNAL ;
    PORT
      LAYER M4 ;
        RECT  26.916 12.24 27 12.264 ;
    END
  END token_cycles[6]
  PIN token_cycles[7]
    DIRECTION OUTPUT ;
    USE SIGNAL ;
    PORT
      LAYER M4 ;
        RECT  26.916 12.384 27 12.408 ;
    END
  END token_cycles[7]
  PIN token_cycles[8]
    DIRECTION OUTPUT ;
    USE SIGNAL ;
    PORT
      LAYER M4 ;
        RECT  26.916 12.528 27 12.552 ;
    END
  END token_cycles[8]
  PIN token_cycles[9]
    DIRECTION OUTPUT ;
    USE SIGNAL ;
    PORT
      LAYER M4 ;
        RECT  26.916 12.672 27 12.696 ;
    END
  END token_cycles[9]
  PIN vgo
    DIRECTION OUTPUT ;
    USE SIGNAL ;
    PORT
      LAYER M4 ;
        RECT  26.916 2.16 27 2.184 ;
    END
  END vgo
  PIN writer_start
    DIRECTION OUTPUT ;
    USE SIGNAL ;
    PORT
      LAYER M4 ;
        RECT  26.916 2.304 27 2.328 ;
    END
  END writer_start
  PIN VDD
    DIRECTION INOUT ;
    USE POWER ;
    PORT
      LAYER M5 ;
        RECT  24.192 2.151 24.312 35.649 ;
        RECT  21.492 2.151 21.612 35.649 ;
        RECT  18.792 2.151 18.912 35.649 ;
        RECT  16.092 2.151 16.212 35.649 ;
        RECT  13.392 2.151 13.512 35.649 ;
        RECT  10.692 2.151 10.812 35.649 ;
        RECT  7.992 2.151 8.112 35.649 ;
        RECT  5.292 2.151 5.412 35.649 ;
        RECT  2.592 2.151 2.712 35.649 ;
    END
  END VDD
  PIN VSS
    DIRECTION INOUT ;
    USE GROUND ;
    PORT
      LAYER M5 ;
        RECT  24 2.137 24.12 35.663 ;
        RECT  21.3 2.137 21.42 35.663 ;
        RECT  18.6 2.137 18.72 35.663 ;
        RECT  15.9 2.137 16.02 35.663 ;
        RECT  13.2 2.137 13.32 35.663 ;
        RECT  10.5 2.137 10.62 35.663 ;
        RECT  7.8 2.137 7.92 35.663 ;
        RECT  5.1 2.137 5.22 35.663 ;
        RECT  2.4 2.137 2.52 35.663 ;
    END
  END VSS
  # OT_OBS_CLOSED layer=M5 d_um=1.536 added=55
  OBS
    LAYER RVTN ;
     RECT  2.16 2.16 24.84 2.295 ;
     RECT  2.16 2.565 24.84 2.835 ;
     RECT  2.16 3.105 24.84 3.375 ;
     RECT  2.16 3.645 24.84 3.915 ;
     RECT  2.16 4.185 24.84 4.455 ;
     RECT  2.16 4.725 24.84 4.995 ;
     RECT  2.16 5.265 24.84 5.535 ;
     RECT  2.16 5.805 24.84 6.075 ;
     RECT  2.16 6.345 24.84 6.615 ;
     RECT  2.16 6.885 24.84 7.155 ;
     RECT  2.16 7.425 24.84 7.695 ;
     RECT  2.16 7.965 24.84 8.235 ;
     RECT  2.16 8.505 24.84 8.775 ;
     RECT  2.16 9.045 24.84 9.315 ;
     RECT  2.16 9.585 24.84 9.855 ;
     RECT  2.16 10.125 24.84 10.395 ;
     RECT  2.16 10.665 24.84 10.935 ;
     RECT  2.16 11.205 24.84 11.475 ;
     RECT  2.16 11.745 24.84 12.015 ;
     RECT  2.16 12.285 24.84 12.555 ;
     RECT  2.16 12.825 24.84 13.095 ;
     RECT  2.16 13.365 24.84 13.635 ;
     RECT  2.16 13.905 24.84 14.175 ;
     RECT  2.16 14.445 24.84 14.715 ;
     RECT  2.16 14.985 24.84 15.255 ;
     RECT  2.16 15.525 24.84 15.795 ;
     RECT  2.16 16.065 24.84 16.335 ;
     RECT  2.16 16.605 24.84 16.875 ;
     RECT  2.16 17.145 24.84 17.415 ;
     RECT  2.16 17.685 24.84 17.955 ;
     RECT  2.16 18.225 24.84 18.495 ;
     RECT  2.16 18.765 24.84 19.035 ;
     RECT  2.16 19.305 24.84 19.575 ;
     RECT  2.16 19.845 24.84 20.115 ;
     RECT  2.16 20.385 24.84 20.655 ;
     RECT  2.16 20.925 24.84 21.195 ;
     RECT  2.16 21.465 24.84 21.735 ;
     RECT  2.16 22.005 24.84 22.275 ;
     RECT  2.16 22.545 24.84 22.815 ;
     RECT  2.16 23.085 24.84 23.355 ;
     RECT  2.16 23.625 24.84 23.895 ;
     RECT  2.16 24.165 24.84 24.435 ;
     RECT  2.16 24.705 24.84 24.975 ;
     RECT  2.16 25.245 24.84 25.515 ;
     RECT  2.16 25.785 24.84 26.055 ;
     RECT  2.16 26.325 24.84 26.595 ;
     RECT  2.16 26.865 24.84 27.135 ;
     RECT  2.16 27.405 24.84 27.675 ;
     RECT  2.16 27.945 24.84 28.215 ;
     RECT  2.16 28.485 24.84 28.755 ;
     RECT  2.16 29.025 24.84 29.295 ;
     RECT  2.16 29.565 24.84 29.835 ;
     RECT  2.16 30.105 24.84 30.375 ;
     RECT  2.16 30.645 24.84 30.915 ;
     RECT  2.16 31.185 24.84 31.455 ;
     RECT  2.16 31.725 24.84 31.995 ;
     RECT  2.16 32.265 24.84 32.535 ;
     RECT  2.16 32.805 24.84 33.075 ;
     RECT  2.16 33.345 24.84 33.615 ;
     RECT  2.16 33.885 24.84 34.155 ;
     RECT  2.16 34.425 24.84 34.695 ;
     RECT  2.16 34.965 24.84 35.235 ;
     RECT  2.16 35.505 24.84 35.64 ;
    LAYER RVTP ;
     RECT  2.16 2.295 24.84 2.565 ;
     RECT  2.16 2.835 24.84 3.105 ;
     RECT  2.16 3.375 24.84 3.645 ;
     RECT  2.16 3.915 24.84 4.185 ;
     RECT  2.16 4.455 24.84 4.725 ;
     RECT  2.16 4.995 24.84 5.265 ;
     RECT  2.16 5.535 24.84 5.805 ;
     RECT  2.16 6.075 24.84 6.345 ;
     RECT  2.16 6.615 24.84 6.885 ;
     RECT  2.16 7.155 24.84 7.425 ;
     RECT  2.16 7.695 24.84 7.965 ;
     RECT  2.16 8.235 24.84 8.505 ;
     RECT  2.16 8.775 24.84 9.045 ;
     RECT  2.16 9.315 24.84 9.585 ;
     RECT  2.16 9.855 24.84 10.125 ;
     RECT  2.16 10.395 24.84 10.665 ;
     RECT  2.16 10.935 24.84 11.205 ;
     RECT  2.16 11.475 24.84 11.745 ;
     RECT  2.16 12.015 24.84 12.285 ;
     RECT  2.16 12.555 24.84 12.825 ;
     RECT  2.16 13.095 24.84 13.365 ;
     RECT  2.16 13.635 24.84 13.905 ;
     RECT  2.16 14.175 24.84 14.445 ;
     RECT  2.16 14.715 24.84 14.985 ;
     RECT  2.16 15.255 24.84 15.525 ;
     RECT  2.16 15.795 24.84 16.065 ;
     RECT  2.16 16.335 24.84 16.605 ;
     RECT  2.16 16.875 24.84 17.145 ;
     RECT  2.16 17.415 24.84 17.685 ;
     RECT  2.16 17.955 24.84 18.225 ;
     RECT  2.16 18.495 24.84 18.765 ;
     RECT  2.16 19.035 24.84 19.305 ;
     RECT  2.16 19.575 24.84 19.845 ;
     RECT  2.16 20.115 24.84 20.385 ;
     RECT  2.16 20.655 24.84 20.925 ;
     RECT  2.16 21.195 24.84 21.465 ;
     RECT  2.16 21.735 24.84 22.005 ;
     RECT  2.16 22.275 24.84 22.545 ;
     RECT  2.16 22.815 24.84 23.085 ;
     RECT  2.16 23.355 24.84 23.625 ;
     RECT  2.16 23.895 24.84 24.165 ;
     RECT  2.16 24.435 24.84 24.705 ;
     RECT  2.16 24.975 24.84 25.245 ;
     RECT  2.16 25.515 24.84 25.785 ;
     RECT  2.16 26.055 24.84 26.325 ;
     RECT  2.16 26.595 24.84 26.865 ;
     RECT  2.16 27.135 24.84 27.405 ;
     RECT  2.16 27.675 24.84 27.945 ;
     RECT  2.16 28.215 24.84 28.485 ;
     RECT  2.16 28.755 24.84 29.025 ;
     RECT  2.16 29.295 24.84 29.565 ;
     RECT  2.16 29.835 24.84 30.105 ;
     RECT  2.16 30.375 24.84 30.645 ;
     RECT  2.16 30.915 24.84 31.185 ;
     RECT  2.16 31.455 24.84 31.725 ;
     RECT  2.16 31.995 24.84 32.265 ;
     RECT  2.16 32.535 24.84 32.805 ;
     RECT  2.16 33.075 24.84 33.345 ;
     RECT  2.16 33.615 24.84 33.885 ;
     RECT  2.16 34.155 24.84 34.425 ;
     RECT  2.16 34.695 24.84 34.965 ;
     RECT  2.16 35.235 24.84 35.505 ;
    LAYER M1 ;
     RECT  2.16 2.151 24.84 35.649 ;
    LAYER M2 ;
     RECT  0.103 22.788 0.139 22.806 ;
     RECT  0.103 17.082 2.16 17.1 ;
     RECT  0.139 22.59 2.16 22.806 ;
     RECT  2.16 2.151 17.059 35.649 ;
     RECT  17.059 2.106 17.095 35.649 ;
     RECT  17.095 1.962 21.875 35.649 ;
     RECT  21.875 2.034 22.415 35.649 ;
     RECT  22.415 2.106 24.359 35.649 ;
     RECT  24.359 2.151 24.84 35.649 ;
     RECT  24.84 2.502 25.079 3.834 ;
     RECT  24.84 6.822 25.079 22.734 ;
     RECT  25.079 2.736 25.115 3.834 ;
     RECT  25.079 10.908 25.295 13.968 ;
     RECT  25.079 14.886 25.547 22.734 ;
     RECT  24.84 28.188 25.547 32.184 ;
     RECT  25.115 3.006 25.583 3.834 ;
     RECT  25.583 3.006 25.655 3.744 ;
     RECT  25.079 6.822 25.655 9.954 ;
     RECT  25.295 10.908 25.655 11.232 ;
     RECT  25.547 28.386 25.655 32.184 ;
     RECT  25.655 6.822 25.691 7.884 ;
     RECT  25.295 12.366 25.691 13.968 ;
     RECT  25.655 8.82 25.727 9.954 ;
     RECT  25.655 28.926 25.943 32.184 ;
     RECT  25.943 28.926 26.015 31.914 ;
     RECT  26.015 28.926 26.087 31.482 ;
     RECT  26.087 28.926 26.123 30.744 ;
     RECT  25.691 7.056 26.195 7.884 ;
     RECT  25.547 14.886 26.195 18.594 ;
     RECT  25.547 19.476 26.195 22.734 ;
     RECT  24.84 23.526 26.195 26.784 ;
     RECT  24.84 5.004 26.231 5.796 ;
     RECT  26.195 7.056 26.231 7.794 ;
     RECT  26.195 15.426 26.231 18.594 ;
     RECT  26.195 19.476 26.231 21.924 ;
     RECT  26.195 22.716 26.231 22.734 ;
     RECT  26.123 28.926 26.231 30.294 ;
     RECT  25.655 3.114 26.267 3.744 ;
     RECT  26.231 7.776 26.267 7.794 ;
     RECT  25.727 9.09 26.267 9.954 ;
     RECT  25.655 11.106 26.267 11.232 ;
     RECT  26.231 15.534 26.267 18.594 ;
     RECT  26.231 19.818 26.267 21.762 ;
     RECT  26.195 23.67 26.267 26.784 ;
     RECT  26.267 3.114 26.303 3.474 ;
     RECT  26.267 9.126 26.303 9.954 ;
     RECT  25.691 12.366 26.303 13.734 ;
     RECT  26.267 15.534 26.303 16.902 ;
     RECT  26.267 20.466 26.303 21.564 ;
     RECT  26.231 29.106 26.303 30.294 ;
     RECT  26.303 3.186 26.339 3.474 ;
     RECT  26.303 9.126 26.339 9.144 ;
     RECT  26.303 13.374 26.339 13.734 ;
     RECT  26.303 16.11 26.339 16.902 ;
     RECT  26.303 21.006 26.339 21.564 ;
     RECT  26.267 23.67 26.339 25.974 ;
     RECT  26.339 3.348 26.375 3.474 ;
     RECT  26.339 24.984 26.375 25.974 ;
     RECT  26.375 3.348 26.411 3.366 ;
     RECT  26.339 16.146 26.411 16.902 ;
     RECT  26.339 23.67 26.411 23.994 ;
     RECT  26.375 24.984 26.447 25.002 ;
     RECT  26.231 5.004 26.843 5.634 ;
     RECT  26.375 25.956 26.843 25.974 ;
     RECT  26.303 30.276 26.843 30.294 ;
     RECT  26.843 5.346 26.879 5.634 ;
     RECT  26.303 29.106 26.879 29.394 ;
     RECT  26.879 5.616 26.915 5.634 ;
     RECT  26.303 9.936 26.915 9.954 ;
     RECT  26.267 11.106 26.915 11.124 ;
     RECT  26.303 12.366 26.915 12.384 ;
     RECT  26.339 13.716 26.915 13.734 ;
     RECT  26.411 16.236 26.915 16.902 ;
     RECT  26.267 17.964 26.915 17.982 ;
     RECT  26.339 21.546 26.915 21.564 ;
     RECT  26.815 22.824 26.915 22.842 ;
     RECT  26.411 23.67 26.915 23.688 ;
     RECT  26.267 26.766 26.915 26.784 ;
     RECT  26.879 29.376 26.915 29.394 ;
    LAYER M3 ;
     RECT  24.372 0.715 24.39 0.859 ;
     RECT  26.244 1.003 26.262 1.147 ;
     RECT  24.372 0.859 25.074 1.291 ;
     RECT  26.244 1.147 26.298 1.291 ;
     RECT  24.372 1.291 26.298 1.435 ;
     RECT  24.372 1.435 26.334 1.579 ;
     RECT  24.372 1.579 26.37 1.723 ;
     RECT  21.852 1.957 21.87 2.029 ;
     RECT  17.1 1.957 17.118 2.101 ;
     RECT  21.852 2.029 22.41 2.101 ;
     RECT  24.372 1.723 26.406 2.101 ;
     RECT  18.9 2.101 18.918 2.143 ;
     RECT  21.456 2.101 22.41 2.143 ;
     RECT  24.336 2.101 26.406 2.143 ;
     RECT  15.915 2.143 16.005 2.191 ;
     RECT  21.315 2.143 22.41 2.191 ;
     RECT  24.015 2.143 26.406 2.263 ;
     RECT  9.216 0.571 9.234 2.291 ;
     RECT  15.804 2.191 16.005 2.299 ;
     RECT  17.064 2.101 17.118 2.299 ;
     RECT  18.615 2.143 18.918 2.299 ;
     RECT  20.304 2.029 20.322 2.299 ;
     RECT  21.315 2.191 22.986 2.299 ;
     RECT  15.804 2.299 17.118 2.335 ;
     RECT  18.18 2.299 20.322 2.335 ;
     RECT  21.168 2.299 22.986 2.335 ;
     RECT  15.48 2.335 22.986 2.371 ;
     RECT  23.832 2.263 26.406 2.371 ;
     RECT  2.415 2.143 2.505 2.413 ;
     RECT  5.115 2.143 5.205 2.413 ;
     RECT  7.815 2.143 7.905 2.413 ;
     RECT  10.515 2.143 10.605 2.413 ;
     RECT  13.215 2.143 13.305 2.413 ;
     RECT  15.48 2.371 26.406 2.605 ;
     RECT  13.215 2.413 13.497 2.731 ;
     RECT  15.372 2.605 26.406 2.731 ;
     RECT  15.192 2.731 26.406 2.759 ;
     RECT  12.96 2.731 13.497 2.803 ;
     RECT  14.4 2.371 14.418 2.803 ;
     RECT  14.22 2.803 14.418 2.839 ;
     RECT  15.192 2.759 24.75 2.839 ;
     RECT  9.576 2.371 9.594 2.911 ;
     RECT  10.515 2.413 10.797 3.001 ;
     RECT  12.456 2.803 13.497 3.001 ;
     RECT  14.22 2.839 24.75 3.001 ;
     RECT  9.576 2.911 9.738 3.029 ;
     RECT  10.515 3.001 24.75 3.181 ;
     RECT  10.44 3.181 24.75 3.335 ;
     RECT  25.56 2.759 26.406 3.371 ;
     RECT  9.504 3.181 9.522 3.379 ;
     RECT  9.432 3.379 9.522 3.389 ;
     RECT  2.415 2.413 2.697 3.415 ;
     RECT  2.415 3.415 3.15 3.451 ;
     RECT  25.56 3.371 26.37 3.479 ;
     RECT  2.415 3.451 3.618 3.541 ;
     RECT  5.115 2.413 5.397 3.541 ;
     RECT  2.415 3.541 4.302 3.577 ;
     RECT  5.115 3.541 5.562 3.577 ;
     RECT  2.415 3.577 5.562 3.685 ;
     RECT  7.815 2.413 8.097 3.721 ;
     RECT  25.56 3.479 26.262 3.749 ;
     RECT  25.56 3.749 25.578 3.839 ;
     RECT  2.304 3.685 5.562 3.955 ;
     RECT  6.372 3.883 6.39 3.955 ;
     RECT  7.2 3.721 8.097 3.991 ;
     RECT  10.515 3.335 24.75 4.109 ;
     RECT  22.788 4.109 24.75 4.217 ;
     RECT  2.304 3.955 6.39 4.219 ;
     RECT  7.2 3.991 8.406 4.219 ;
     RECT  23.184 4.217 24.75 4.379 ;
     RECT  10.515 4.109 21.798 4.415 ;
     RECT  9.432 3.389 9.45 4.621 ;
     RECT  10.515 4.415 19.602 4.621 ;
     RECT  2.304 4.219 8.406 4.693 ;
     RECT  23.184 4.379 24.642 4.793 ;
     RECT  2.304 4.693 8.55 4.927 ;
     RECT  2.304 4.927 8.586 5.071 ;
     RECT  9.432 4.621 19.602 5.071 ;
     RECT  20.34 4.415 21.798 5.071 ;
     RECT  26.82 4.999 26.838 5.071 ;
     RECT  2.304 5.071 19.602 5.341 ;
     RECT  20.34 5.071 22.158 5.341 ;
     RECT  26.208 5.071 26.838 5.341 ;
     RECT  23.184 4.793 24.498 5.459 ;
     RECT  26.208 5.341 26.874 5.467 ;
     RECT  0.324 5.323 0.342 5.501 ;
     RECT  23.472 5.459 24.498 5.539 ;
     RECT  25.632 5.467 26.874 5.567 ;
     RECT  26.208 5.567 26.874 5.611 ;
     RECT  23.472 5.539 24.642 5.639 ;
     RECT  2.304 5.341 22.158 5.845 ;
     RECT  2.304 5.845 22.374 5.881 ;
     RECT  26.208 5.611 26.91 6.077 ;
     RECT  26.208 6.077 26.874 6.221 ;
     RECT  23.472 5.639 24.534 6.341 ;
     RECT  2.304 5.881 22.734 6.421 ;
     RECT  26.208 6.221 26.262 6.619 ;
     RECT  26.172 6.619 26.262 6.763 ;
     RECT  2.304 6.421 23.13 7.051 ;
     RECT  2.268 7.051 23.13 7.115 ;
     RECT  23.904 6.341 24.534 7.189 ;
     RECT  25.488 6.763 26.262 7.189 ;
     RECT  23.904 7.189 26.262 7.229 ;
     RECT  2.304 7.115 23.13 7.231 ;
     RECT  23.904 7.229 24.534 7.231 ;
     RECT  2.304 7.231 24.534 7.799 ;
     RECT  25.56 7.229 26.262 7.799 ;
     RECT  25.56 7.799 26.19 7.889 ;
     RECT  2.304 7.799 22.914 7.925 ;
     RECT  2.304 7.925 22.518 8.059 ;
     RECT  2.268 8.059 22.518 8.303 ;
     RECT  23.832 7.799 24.534 8.473 ;
     RECT  25.56 7.889 25.65 8.491 ;
     RECT  2.415 8.303 22.518 8.501 ;
     RECT  2.415 8.501 4.086 8.537 ;
     RECT  25.452 8.491 25.65 8.779 ;
     RECT  25.452 8.779 25.722 8.923 ;
     RECT  23.832 8.473 24.606 8.941 ;
     RECT  4.068 8.537 4.086 8.969 ;
     RECT  2.415 8.537 3.33 9.005 ;
     RECT  23.724 8.941 24.606 9.013 ;
     RECT  25.452 8.923 26.262 9.013 ;
     RECT  23.724 9.013 26.262 9.067 ;
     RECT  23.724 9.067 26.298 9.077 ;
     RECT  26.172 9.077 26.298 9.121 ;
     RECT  4.86 8.501 22.518 9.211 ;
     RECT  23.724 9.077 25.146 9.211 ;
     RECT  4.86 9.211 25.146 9.283 ;
     RECT  4.788 9.283 25.146 9.815 ;
     RECT  26.172 9.121 26.334 9.931 ;
     RECT  4.824 9.815 25.146 9.965 ;
     RECT  26.172 9.931 26.91 10.109 ;
     RECT  4.824 9.965 25.074 10.541 ;
     RECT  4.824 10.541 24.714 10.561 ;
     RECT  3.996 10.561 4.014 10.741 ;
     RECT  25.524 10.903 25.65 11.209 ;
     RECT  26.892 10.109 26.91 11.209 ;
     RECT  25.524 11.209 26.91 11.261 ;
     RECT  3.888 10.741 4.014 11.371 ;
     RECT  4.788 10.561 24.714 11.371 ;
     RECT  3.888 11.371 24.714 11.713 ;
     RECT  3.888 11.713 25.29 12.413 ;
     RECT  26.244 11.261 26.91 12.451 ;
     RECT  25.668 12.451 26.91 12.845 ;
     RECT  3.888 12.413 24.57 12.865 ;
     RECT  25.668 12.845 26.334 12.989 ;
     RECT  2.415 9.005 2.697 13.261 ;
     RECT  3.564 12.865 24.57 13.261 ;
     RECT  2.415 13.261 24.57 13.387 ;
     RECT  2.415 13.387 25.074 13.469 ;
     RECT  26.172 12.989 26.334 13.675 ;
     RECT  26.172 13.675 26.91 13.739 ;
     RECT  26.172 13.739 26.262 13.853 ;
     RECT  2.415 13.469 24.606 13.945 ;
     RECT  26.172 13.853 26.226 13.945 ;
     RECT  25.668 13.945 26.226 13.997 ;
     RECT  2.304 13.945 24.606 14.251 ;
     RECT  2.304 14.251 25.074 14.477 ;
     RECT  26.172 13.997 26.226 14.827 ;
     RECT  26.172 14.827 26.262 15.115 ;
     RECT  26.172 15.115 26.298 15.259 ;
     RECT  2.304 14.477 24.57 15.403 ;
     RECT  2.304 15.403 25.074 15.547 ;
     RECT  26.172 15.259 26.334 15.547 ;
     RECT  2.304 15.547 26.334 15.593 ;
     RECT  25.668 15.593 26.334 15.691 ;
     RECT  25.668 15.691 26.91 15.827 ;
     RECT  2.304 15.593 24.534 16.411 ;
     RECT  26.208 15.827 26.91 16.907 ;
     RECT  2.304 16.411 25.074 17.077 ;
     RECT  0.108 17.077 0.126 17.165 ;
     RECT  2.268 17.077 25.074 17.221 ;
     RECT  26.208 16.907 26.262 17.221 ;
     RECT  2.268 17.221 26.262 17.753 ;
     RECT  26.892 17.959 26.91 18.029 ;
     RECT  2.268 17.753 25.686 18.565 ;
     RECT  2.268 18.565 26.262 18.869 ;
     RECT  2.268 18.869 25.074 18.893 ;
     RECT  26.208 18.869 26.262 19.499 ;
     RECT  2.304 18.893 25.074 19.613 ;
     RECT  26.244 19.499 26.262 19.723 ;
     RECT  0.144 19.771 0.162 19.901 ;
     RECT  2.304 19.613 24.534 19.901 ;
     RECT  26.244 19.723 26.298 20.155 ;
     RECT  26.244 20.155 26.334 20.299 ;
     RECT  2.304 19.901 24.297 20.425 ;
     RECT  25.632 20.299 26.334 20.723 ;
     RECT  2.268 20.425 24.297 20.965 ;
     RECT  25.668 20.723 26.334 21.191 ;
     RECT  2.268 20.965 24.39 21.227 ;
     RECT  2.304 21.227 24.39 21.235 ;
     RECT  26.172 21.191 26.334 21.307 ;
     RECT  0.144 21.307 0.162 21.437 ;
     RECT  26.172 21.307 26.91 21.569 ;
     RECT  2.304 21.235 24.498 21.739 ;
     RECT  2.304 21.739 25.11 21.839 ;
     RECT  26.172 21.569 26.262 22.081 ;
     RECT  2.304 21.839 24.534 22.171 ;
     RECT  25.452 22.081 26.262 22.205 ;
     RECT  26.172 22.205 26.262 22.747 ;
     RECT  0.144 22.585 0.162 22.783 ;
     RECT  0.108 22.783 0.162 23.309 ;
     RECT  2.268 22.171 24.534 23.315 ;
     RECT  0.108 23.309 0.126 23.501 ;
     RECT  2.304 23.315 24.534 23.585 ;
     RECT  26.172 22.747 26.91 24.043 ;
     RECT  26.028 24.043 26.91 24.187 ;
     RECT  2.304 23.585 24.39 24.331 ;
     RECT  2.304 24.331 24.534 24.745 ;
     RECT  25.344 24.187 26.91 24.745 ;
     RECT  0.144 24.955 0.162 25.661 ;
     RECT  2.304 24.745 26.91 26.491 ;
     RECT  2.268 26.491 26.91 27.905 ;
     RECT  0.108 27.787 0.126 27.917 ;
     RECT  2.304 27.905 26.91 28.175 ;
     RECT  2.415 28.175 26.91 28.985 ;
     RECT  3.492 28.985 26.91 29.057 ;
     RECT  3.6 29.057 26.91 29.399 ;
     RECT  3.6 29.399 26.838 30.299 ;
     RECT  3.6 30.299 26.118 30.749 ;
     RECT  2.415 28.985 2.697 30.955 ;
     RECT  3.6 30.749 26.082 30.955 ;
     RECT  2.415 30.955 26.082 31.225 ;
     RECT  2.304 31.225 26.082 31.379 ;
     RECT  2.304 31.379 24.678 31.451 ;
     RECT  25.92 31.379 26.082 31.487 ;
     RECT  25.92 31.487 26.01 31.919 ;
     RECT  2.304 31.451 24.498 31.955 ;
     RECT  25.92 31.919 25.938 32.189 ;
     RECT  2.304 31.955 24.297 32.339 ;
     RECT  2.304 32.339 9.09 32.531 ;
     RECT  2.34 32.531 9.09 32.765 ;
     RECT  9.9 32.339 24.297 32.999 ;
     RECT  9.9 32.999 23.202 33.035 ;
     RECT  2.415 32.765 9.09 33.071 ;
     RECT  2.415 33.071 4.302 33.269 ;
     RECT  2.415 33.269 3.33 33.305 ;
     RECT  4.14 33.269 4.158 33.305 ;
     RECT  5.076 33.071 9.09 33.349 ;
     RECT  9.9 33.035 22.986 33.349 ;
     RECT  5.076 33.349 22.986 33.413 ;
     RECT  5.076 33.413 6.678 33.611 ;
     RECT  7.416 33.413 22.986 33.611 ;
     RECT  5.115 33.611 6.678 34.195 ;
     RECT  7.416 33.611 22.698 34.195 ;
     RECT  5.115 34.195 22.698 34.457 ;
     RECT  5.115 34.457 14.706 34.465 ;
     RECT  15.516 34.457 22.698 34.501 ;
     RECT  5.076 34.465 14.706 34.655 ;
     RECT  15.516 34.501 22.842 34.763 ;
     RECT  22.824 34.763 22.842 34.771 ;
     RECT  15.516 34.763 21.69 34.889 ;
     RECT  22.824 34.771 23.022 34.889 ;
     RECT  23.004 34.889 23.022 34.961 ;
     RECT  15.516 34.889 19.818 35.033 ;
     RECT  15.516 35.033 18.897 35.069 ;
     RECT  19.8 35.033 19.818 35.069 ;
     RECT  20.628 34.889 21.597 35.069 ;
     RECT  5.115 34.655 14.706 35.159 ;
     RECT  15.552 35.069 18.897 35.159 ;
     RECT  15.66 35.159 16.83 35.213 ;
     RECT  5.115 35.159 11.25 35.231 ;
     RECT  15.66 35.213 16.197 35.231 ;
     RECT  6.984 35.231 11.25 35.267 ;
     RECT  12.132 35.159 14.706 35.267 ;
     RECT  6.984 35.267 8.55 35.303 ;
     RECT  12.132 35.267 12.222 35.303 ;
     RECT  12.996 35.267 14.706 35.312 ;
     RECT  7.452 35.303 8.478 35.339 ;
     RECT  2.415 33.305 2.697 35.387 ;
     RECT  5.115 35.231 6.174 35.387 ;
     RECT  15.915 35.231 16.197 35.387 ;
     RECT  18.615 35.159 18.897 35.387 ;
     RECT  21.315 35.069 21.597 35.387 ;
     RECT  24.015 32.999 24.297 35.387 ;
     RECT  6.048 35.387 6.174 35.429 ;
     RECT  7.452 35.339 8.406 35.429 ;
     RECT  9.54 35.267 11.25 35.429 ;
     RECT  12.132 35.303 12.15 35.429 ;
     RECT  13.104 35.312 14.706 35.429 ;
     RECT  7.452 35.429 7.905 35.453 ;
     RECT  6.048 35.429 6.066 35.465 ;
     RECT  9.54 35.429 9.558 35.465 ;
     RECT  10.515 35.429 11.178 35.465 ;
     RECT  13.104 35.429 13.77 35.465 ;
     RECT  13.104 35.465 13.305 35.573 ;
     RECT  2.415 35.387 2.505 35.657 ;
     RECT  5.115 35.387 5.205 35.657 ;
     RECT  7.815 35.453 7.905 35.657 ;
     RECT  10.515 35.465 10.605 35.657 ;
     RECT  13.215 35.573 13.305 35.657 ;
     RECT  15.915 35.387 16.005 35.657 ;
     RECT  18.615 35.387 18.705 35.657 ;
     RECT  21.315 35.387 21.405 35.657 ;
     RECT  24.015 35.387 24.105 35.657 ;
    LAYER M4 ;
     RECT  0.084 14.112 0.097 14.136 ;
     RECT  0.06 14.136 0.097 14.256 ;
     RECT  0.084 14.256 0.097 14.28 ;
     RECT  0.06 14.28 0.097 14.4 ;
     RECT  0.084 14.4 0.097 14.424 ;
     RECT  0.06 14.424 0.097 14.544 ;
     RECT  0.084 14.544 0.097 14.568 ;
     RECT  0.06 14.568 0.097 14.688 ;
     RECT  0.084 14.688 0.097 14.712 ;
     RECT  0.06 14.712 0.097 14.832 ;
     RECT  0.084 14.832 0.097 14.856 ;
     RECT  0.06 14.856 0.097 14.976 ;
     RECT  0.084 14.976 0.097 15 ;
     RECT  0.06 15 0.097 15.12 ;
     RECT  0.084 15.12 0.097 15.144 ;
     RECT  0.06 15.144 0.097 15.264 ;
     RECT  0.084 15.264 0.097 15.288 ;
     RECT  0.06 15.288 0.097 15.408 ;
     RECT  0.084 15.408 0.097 15.432 ;
     RECT  0.06 15.432 0.097 15.552 ;
     RECT  0.084 15.552 0.097 15.576 ;
     RECT  0.06 15.576 0.097 15.696 ;
     RECT  0.084 15.696 0.097 15.72 ;
     RECT  0.06 15.72 0.097 15.84 ;
     RECT  0.084 15.84 0.097 15.864 ;
     RECT  0.06 15.864 0.097 15.984 ;
     RECT  0.084 15.984 0.097 16.008 ;
     RECT  0.06 16.008 0.097 16.128 ;
     RECT  0.084 16.128 0.097 16.152 ;
     RECT  0.06 16.152 0.097 16.272 ;
     RECT  0.084 16.272 0.097 16.296 ;
     RECT  0.06 16.296 0.097 16.416 ;
     RECT  0.084 16.416 0.097 16.44 ;
     RECT  0.06 16.44 0.097 16.56 ;
     RECT  0.084 16.56 0.097 16.584 ;
     RECT  0.06 16.584 0.097 16.704 ;
     RECT  0.084 16.704 0.097 16.728 ;
     RECT  0.06 16.728 0.097 16.848 ;
     RECT  0.084 16.848 0.097 16.872 ;
     RECT  0.06 16.872 0.097 16.992 ;
     RECT  0.084 16.992 0.097 17.016 ;
     RECT  0.06 17.016 0.097 17.136 ;
     RECT  0.084 17.136 0.097 17.16 ;
     RECT  0.06 17.16 0.097 17.28 ;
     RECT  0.084 17.28 0.097 17.304 ;
     RECT  0.06 17.304 0.097 17.424 ;
     RECT  0.084 17.424 0.097 17.448 ;
     RECT  0.06 17.448 0.097 17.568 ;
     RECT  0.084 17.568 0.097 17.592 ;
     RECT  0.06 17.592 0.097 17.712 ;
     RECT  0.084 17.712 0.097 17.736 ;
     RECT  0.06 17.736 0.097 17.856 ;
     RECT  0.084 17.856 0.097 17.88 ;
     RECT  0.06 17.88 0.097 18 ;
     RECT  0.084 18 0.097 18.024 ;
     RECT  0.06 18.024 0.097 18.144 ;
     RECT  0.084 18.144 0.097 18.168 ;
     RECT  0.06 18.168 0.097 18.288 ;
     RECT  0.084 18.288 0.097 18.312 ;
     RECT  0.06 18.312 0.097 18.432 ;
     RECT  0.084 18.432 0.097 18.456 ;
     RECT  0.06 18.456 0.097 18.576 ;
     RECT  0.084 18.576 0.097 18.6 ;
     RECT  0.06 18.6 0.097 18.72 ;
     RECT  0.084 18.72 0.097 18.744 ;
     RECT  0.06 18.744 0.097 18.864 ;
     RECT  0.084 18.864 0.097 18.888 ;
     RECT  0.06 18.888 0.097 19.008 ;
     RECT  0.084 19.008 0.097 19.032 ;
     RECT  0.06 19.032 0.097 19.152 ;
     RECT  0.084 19.152 0.097 19.176 ;
     RECT  0.06 19.176 0.097 19.296 ;
     RECT  0.084 19.296 0.097 19.32 ;
     RECT  0.06 19.32 0.097 19.44 ;
     RECT  0.084 19.44 0.097 19.464 ;
     RECT  0.06 19.464 0.097 19.584 ;
     RECT  0.084 19.584 0.097 19.608 ;
     RECT  0.06 19.608 0.097 19.728 ;
     RECT  0.084 19.728 0.097 19.752 ;
     RECT  0.06 19.752 0.097 19.872 ;
     RECT  0.084 19.872 0.097 19.896 ;
     RECT  0.06 19.896 0.097 20.016 ;
     RECT  0.084 20.016 0.097 20.04 ;
     RECT  0.06 20.04 0.097 20.16 ;
     RECT  0.084 20.16 0.097 20.184 ;
     RECT  0.06 20.184 0.097 20.304 ;
     RECT  0.084 20.304 0.097 20.328 ;
     RECT  0.06 20.328 0.097 20.448 ;
     RECT  0.084 20.448 0.097 20.472 ;
     RECT  0.06 20.472 0.097 20.592 ;
     RECT  0.084 20.592 0.097 20.616 ;
     RECT  0.06 20.616 0.097 20.736 ;
     RECT  0.084 20.736 0.097 20.76 ;
     RECT  0.06 20.76 0.097 20.88 ;
     RECT  0.084 20.88 0.097 20.904 ;
     RECT  0.06 20.904 0.097 21.024 ;
     RECT  0.084 21.024 0.097 21.048 ;
     RECT  0.06 21.048 0.097 21.168 ;
     RECT  0.084 21.168 0.097 21.192 ;
     RECT  0.06 21.192 0.097 21.312 ;
     RECT  0.084 21.312 0.097 21.336 ;
     RECT  0.06 21.336 0.097 21.456 ;
     RECT  0.084 21.456 0.097 21.48 ;
     RECT  0.06 21.48 0.097 21.6 ;
     RECT  0.084 21.6 0.097 21.624 ;
     RECT  0.06 21.624 0.097 21.744 ;
     RECT  0.084 21.744 0.097 21.768 ;
     RECT  0.06 21.768 0.097 21.888 ;
     RECT  0.084 21.888 0.097 21.912 ;
     RECT  0.06 21.912 0.097 22.032 ;
     RECT  0.084 22.032 0.097 22.056 ;
     RECT  0.06 22.056 0.097 22.176 ;
     RECT  0.084 22.176 0.097 22.2 ;
     RECT  0.06 22.2 0.097 22.32 ;
     RECT  0.084 22.32 0.097 22.344 ;
     RECT  0.06 22.344 0.097 22.464 ;
     RECT  0.084 22.464 0.097 22.488 ;
     RECT  0.06 22.488 0.097 22.608 ;
     RECT  0.084 22.608 0.097 22.632 ;
     RECT  0.06 22.632 0.097 22.752 ;
     RECT  0.084 22.752 0.097 22.776 ;
     RECT  0.06 22.776 0.097 22.896 ;
     RECT  0.084 22.896 0.097 22.92 ;
     RECT  0.06 22.92 0.097 23.04 ;
     RECT  0.084 23.04 0.097 23.064 ;
     RECT  0.06 23.064 0.097 23.184 ;
     RECT  0.084 23.184 0.097 23.208 ;
     RECT  0.06 23.208 0.097 23.328 ;
     RECT  0.084 23.328 0.097 23.352 ;
     RECT  0.06 23.352 0.097 23.472 ;
     RECT  0.084 23.472 0.097 23.496 ;
     RECT  0.06 23.496 0.097 23.616 ;
     RECT  0.084 23.616 0.097 23.64 ;
     RECT  0.06 23.64 0.097 23.76 ;
     RECT  0.084 23.76 0.097 23.784 ;
     RECT  0.06 23.784 0.097 23.904 ;
     RECT  0.084 23.904 0.097 23.928 ;
     RECT  0.06 23.928 0.097 24.048 ;
     RECT  0.084 24.048 0.097 24.072 ;
     RECT  0.06 24.072 0.097 24.192 ;
     RECT  0.084 24.192 0.097 24.216 ;
     RECT  0.06 24.216 0.097 24.336 ;
     RECT  0.084 24.336 0.097 24.36 ;
     RECT  0.06 24.36 0.097 24.48 ;
     RECT  0.084 24.48 0.097 24.504 ;
     RECT  0.06 24.504 0.097 24.624 ;
     RECT  0.084 24.624 0.097 24.648 ;
     RECT  0.06 24.648 0.097 24.768 ;
     RECT  0.084 24.768 0.097 24.792 ;
     RECT  0.06 24.792 0.097 24.912 ;
     RECT  0.084 24.912 0.097 24.936 ;
     RECT  0.06 24.936 0.097 25.056 ;
     RECT  0.084 25.056 0.097 25.08 ;
     RECT  0.06 25.08 0.097 25.2 ;
     RECT  0.084 25.2 0.097 25.224 ;
     RECT  0.06 25.224 0.097 25.344 ;
     RECT  0.084 25.344 0.097 25.368 ;
     RECT  0.06 25.368 0.097 25.488 ;
     RECT  0.084 25.488 0.097 25.512 ;
     RECT  0.06 25.512 0.097 25.632 ;
     RECT  0.084 25.632 0.097 25.656 ;
     RECT  0.06 25.656 0.097 25.776 ;
     RECT  0.084 25.776 0.097 25.8 ;
     RECT  0.06 25.8 0.097 25.92 ;
     RECT  0.084 25.92 0.097 25.944 ;
     RECT  0.06 25.944 0.097 26.064 ;
     RECT  0.084 26.064 0.097 26.088 ;
     RECT  0.06 26.088 0.097 26.208 ;
     RECT  0.084 26.208 0.097 26.232 ;
     RECT  0.06 26.232 0.097 26.352 ;
     RECT  0.084 26.352 0.097 26.376 ;
     RECT  0.06 26.376 0.097 26.496 ;
     RECT  0.084 26.496 0.097 26.52 ;
     RECT  0.06 26.52 0.097 26.64 ;
     RECT  0.084 26.64 0.097 26.664 ;
     RECT  0.06 26.664 0.097 26.784 ;
     RECT  0.084 26.784 0.097 26.808 ;
     RECT  0.06 26.808 0.097 26.928 ;
     RECT  0.084 26.928 0.097 26.952 ;
     RECT  0.06 26.952 0.097 27.072 ;
     RECT  0.084 27.072 0.097 27.096 ;
     RECT  0.06 27.096 0.097 27.216 ;
     RECT  0.084 27.216 0.097 27.24 ;
     RECT  0.06 27.24 0.097 27.36 ;
     RECT  0.084 27.36 0.097 27.384 ;
     RECT  0.06 27.384 0.097 27.504 ;
     RECT  0.084 27.504 0.097 27.528 ;
     RECT  0.06 27.528 0.097 27.648 ;
     RECT  0.084 27.648 0.097 27.672 ;
     RECT  0.06 27.672 0.097 27.792 ;
     RECT  0.084 27.792 0.097 27.816 ;
     RECT  0.084 3.744 2.408 3.768 ;
     RECT  0.06 3.768 2.408 3.888 ;
     RECT  0.084 3.888 2.408 3.912 ;
     RECT  0.06 3.912 2.408 4.032 ;
     RECT  0.084 4.032 2.408 4.056 ;
     RECT  0.06 4.056 2.408 4.176 ;
     RECT  0.084 4.176 2.408 4.2 ;
     RECT  0.06 4.2 2.408 4.32 ;
     RECT  0.084 4.32 2.408 4.344 ;
     RECT  0.06 4.344 2.408 4.464 ;
     RECT  0.084 4.464 2.408 4.488 ;
     RECT  0.06 4.488 2.408 4.608 ;
     RECT  0.084 4.608 2.408 4.632 ;
     RECT  0.06 4.632 2.408 4.752 ;
     RECT  0.084 4.752 2.408 4.776 ;
     RECT  0.06 4.776 2.408 4.896 ;
     RECT  0.084 4.896 2.408 4.92 ;
     RECT  0.06 4.92 2.408 5.04 ;
     RECT  0.084 5.04 2.408 5.064 ;
     RECT  0.06 5.064 2.408 5.184 ;
     RECT  0.084 5.184 2.408 5.208 ;
     RECT  0.06 5.208 2.408 5.328 ;
     RECT  0.084 5.328 2.408 5.352 ;
     RECT  0.06 5.352 2.408 5.472 ;
     RECT  0.084 5.472 2.408 5.496 ;
     RECT  0.06 5.496 2.408 5.616 ;
     RECT  0.084 5.616 2.408 5.64 ;
     RECT  0.06 5.64 2.408 5.76 ;
     RECT  0.084 5.76 2.408 5.784 ;
     RECT  0.06 5.784 2.408 5.904 ;
     RECT  0.084 5.904 2.408 5.928 ;
     RECT  0.06 5.928 2.408 6.048 ;
     RECT  0.084 6.048 2.408 6.072 ;
     RECT  0.06 6.072 2.408 6.192 ;
     RECT  0.084 6.192 2.408 6.216 ;
     RECT  0.06 6.216 2.408 6.336 ;
     RECT  0.084 6.336 2.408 6.36 ;
     RECT  0.06 6.36 2.408 6.48 ;
     RECT  0.084 6.48 2.408 6.504 ;
     RECT  0.06 6.504 2.408 6.624 ;
     RECT  0.084 6.624 2.408 6.648 ;
     RECT  0.06 6.648 2.408 6.768 ;
     RECT  0.084 6.768 2.408 6.792 ;
     RECT  0.06 6.792 2.408 6.912 ;
     RECT  0.084 6.912 2.408 6.936 ;
     RECT  0.06 6.936 2.408 7.056 ;
     RECT  0.084 7.056 2.408 7.08 ;
     RECT  0.06 7.08 2.408 7.2 ;
     RECT  0.084 7.2 2.408 7.224 ;
     RECT  0.06 7.224 2.408 7.344 ;
     RECT  0.084 7.344 2.408 7.368 ;
     RECT  0.06 7.368 2.408 7.488 ;
     RECT  0.084 7.488 2.408 7.512 ;
     RECT  0.06 7.512 2.408 7.632 ;
     RECT  0.084 7.632 2.408 7.656 ;
     RECT  0.06 7.656 2.408 7.776 ;
     RECT  0.084 7.776 2.408 7.8 ;
     RECT  0.06 7.8 2.408 7.92 ;
     RECT  0.084 7.92 2.408 7.944 ;
     RECT  0.06 7.944 2.408 8.064 ;
     RECT  0.084 8.064 2.408 8.088 ;
     RECT  0.06 8.088 2.408 8.208 ;
     RECT  0.084 8.208 2.408 8.232 ;
     RECT  0.097 14.112 2.408 27.912 ;
     RECT  0.084 31.248 2.408 31.272 ;
     RECT  0.06 31.272 2.408 31.392 ;
     RECT  0.084 31.392 2.408 31.416 ;
     RECT  0.06 31.416 2.408 31.536 ;
     RECT  0.084 31.536 2.408 31.56 ;
     RECT  0.06 31.56 2.408 31.68 ;
     RECT  0.084 31.68 2.408 31.704 ;
     RECT  0.06 31.704 2.408 31.824 ;
     RECT  0.084 31.824 2.408 31.848 ;
     RECT  0.06 31.848 2.408 31.968 ;
     RECT  0.084 31.968 2.408 31.992 ;
     RECT  0.06 31.992 2.408 32.112 ;
     RECT  0.084 32.112 2.408 32.136 ;
     RECT  0.06 32.136 2.408 32.256 ;
     RECT  0.084 32.256 2.408 32.28 ;
     RECT  0.06 32.28 2.408 32.4 ;
     RECT  0.084 32.4 2.408 32.424 ;
     RECT  2.408 2.148 2.512 35.652 ;
     RECT  2.512 2.418 2.704 35.382 ;
     RECT  2.704 19.776 2.729 28.488 ;
     RECT  2.704 4.464 2.765 4.488 ;
     RECT  2.704 5.472 2.765 5.784 ;
     RECT  2.729 19.776 2.765 20.184 ;
     RECT  2.729 21.408 2.765 28.488 ;
     RECT  2.704 15.6 2.837 17.448 ;
     RECT  2.765 19.776 2.909 19.8 ;
     RECT  2.765 21.408 2.945 25.56 ;
     RECT  2.765 5.472 3.017 5.64 ;
     RECT  2.945 21.408 3.017 22.344 ;
     RECT  2.945 23.952 3.017 25.56 ;
     RECT  2.765 26.64 3.341 28.488 ;
     RECT  3.341 28.464 3.521 28.488 ;
     RECT  2.837 17.376 3.697 17.448 ;
     RECT  3.017 21.408 3.841 21.72 ;
     RECT  3.017 23.952 3.917 25.08 ;
     RECT  3.841 21.168 3.949 21.72 ;
     RECT  3.877 10.896 4.025 10.92 ;
     RECT  2.837 15.6 4.057 15.96 ;
     RECT  4.057 32.448 4.129 32.472 ;
     RECT  4.129 25.44 4.165 25.608 ;
     RECT  3.341 26.64 4.165 27.384 ;
     RECT  4.129 32.448 4.165 33.288 ;
     RECT  3.913 7.872 4.201 7.896 ;
     RECT  4.057 15.264 4.237 15.96 ;
     RECT  3.917 23.952 4.417 24.36 ;
     RECT  4.129 13.92 4.489 13.944 ;
     RECT  4.237 15.072 4.489 15.96 ;
     RECT  4.093 6.816 4.525 6.84 ;
     RECT  4.201 7.872 4.525 7.992 ;
     RECT  4.165 25.44 4.561 27.384 ;
     RECT  4.525 28.56 4.561 28.584 ;
     RECT  4.561 25.44 4.597 28.584 ;
     RECT  4.345 29.76 4.597 29.784 ;
     RECT  4.417 23.664 4.633 24.36 ;
     RECT  4.453 19.632 4.705 19.656 ;
     RECT  4.489 13.92 4.741 15.96 ;
     RECT  3.017 5.616 4.777 5.64 ;
     RECT  3.949 21.12 4.813 21.72 ;
     RECT  4.633 22.752 4.813 24.36 ;
     RECT  4.741 13.2 4.849 15.96 ;
     RECT  4.705 19.584 4.849 19.656 ;
     RECT  4.849 19.584 4.885 19.8 ;
     RECT  4.813 21.12 4.885 24.36 ;
     RECT  4.885 19.584 4.921 24.36 ;
     RECT  4.777 5.616 5.108 5.832 ;
     RECT  4.525 6.816 5.108 7.992 ;
     RECT  4.957 9.552 5.108 9.576 ;
     RECT  4.849 13.152 5.108 15.96 ;
     RECT  3.697 17.376 5.108 17.64 ;
     RECT  4.921 18.96 5.108 24.408 ;
     RECT  4.597 25.44 5.108 29.784 ;
     RECT  4.165 32.304 5.108 33.288 ;
     RECT  5.108 2.148 5.212 35.652 ;
     RECT  5.212 2.418 5.404 35.382 ;
     RECT  5.404 13.056 5.465 15.48 ;
     RECT  5.404 5.808 5.501 10.056 ;
     RECT  5.404 30.96 5.537 33.048 ;
     RECT  5.404 11.952 5.581 11.976 ;
     RECT  5.465 13.104 5.609 15.48 ;
     RECT  5.537 31.344 5.651 33.048 ;
     RECT  5.501 9.552 5.933 10.056 ;
     RECT  5.609 13.104 6.005 13.944 ;
     RECT  5.404 16.608 6.227 29.784 ;
     RECT  6.227 16.608 6.293 18.168 ;
     RECT  6.227 19.872 6.293 29.784 ;
     RECT  6.293 23.28 6.323 29.784 ;
     RECT  6.323 29.568 6.329 29.784 ;
     RECT  6.323 23.28 6.365 27.24 ;
     RECT  5.404 4.224 6.433 4.248 ;
     RECT  6.365 23.28 6.473 26.232 ;
     RECT  6.005 13.152 6.545 13.944 ;
     RECT  6.473 23.28 6.617 25.656 ;
     RECT  5.651 31.92 6.617 33.048 ;
     RECT  6.293 16.608 6.649 16.632 ;
     RECT  5.501 5.808 6.721 8.136 ;
     RECT  5.933 9.552 6.721 9.576 ;
     RECT  6.433 4.224 6.757 4.44 ;
     RECT  6.613 34.944 6.829 34.968 ;
     RECT  6.721 5.808 6.833 9.576 ;
     RECT  6.613 11.136 6.86 11.16 ;
     RECT  6.649 16.512 6.86 16.632 ;
     RECT  6.86 10.944 6.901 11.16 ;
     RECT  6.829 34.656 6.937 34.968 ;
     RECT  6.757 4.224 7.153 4.536 ;
     RECT  6.833 5.808 7.153 7.992 ;
     RECT  6.86 16.464 7.333 16.632 ;
     RECT  6.293 18.096 7.333 18.168 ;
     RECT  6.293 19.872 7.333 21.96 ;
     RECT  6.617 32.16 7.429 33.048 ;
     RECT  7.153 4.224 7.436 7.992 ;
     RECT  6.329 29.76 7.441 29.784 ;
     RECT  7.429 32.16 7.441 33.24 ;
     RECT  6.937 34.368 7.441 34.968 ;
     RECT  7.333 16.464 7.477 18.168 ;
     RECT  5.609 15.264 7.621 15.48 ;
     RECT  7.477 16.464 7.621 18.264 ;
     RECT  7.441 29.76 7.649 30.36 ;
     RECT  7.441 32.16 7.649 33.384 ;
     RECT  6.545 13.632 7.729 13.944 ;
     RECT  7.436 3.936 7.808 7.992 ;
     RECT  6.833 9.552 7.808 9.576 ;
     RECT  6.901 10.944 7.808 11.256 ;
     RECT  7.729 12.576 7.808 13.944 ;
     RECT  7.621 15.264 7.808 18.264 ;
     RECT  7.333 19.68 7.808 21.96 ;
     RECT  6.617 23.28 7.808 23.448 ;
     RECT  6.617 24.48 7.808 25.656 ;
     RECT  7.649 29.76 7.808 33.384 ;
     RECT  7.441 34.368 7.808 35.448 ;
     RECT  7.808 2.148 7.912 35.652 ;
     RECT  7.912 2.418 8.104 35.448 ;
     RECT  8.104 34.656 8.201 35.448 ;
     RECT  8.104 29.04 8.243 33.384 ;
     RECT  8.104 4.416 8.309 7.992 ;
     RECT  8.104 17.664 8.339 21.672 ;
     RECT  8.243 31.488 8.489 33.384 ;
     RECT  8.104 9.024 8.561 9.048 ;
     RECT  8.309 4.416 8.597 7.368 ;
     RECT  8.339 17.664 8.813 19.848 ;
     RECT  8.104 23.136 8.813 24.648 ;
     RECT  8.104 12.576 8.915 16.104 ;
     RECT  8.104 11.136 9.097 11.256 ;
     RECT  8.915 12.576 9.097 12.84 ;
     RECT  8.813 17.664 9.097 18.168 ;
     RECT  8.339 20.88 9.101 21.672 ;
     RECT  8.813 23.136 9.109 24.504 ;
     RECT  9.097 10.08 9.133 10.104 ;
     RECT  9.097 11.136 9.133 12.84 ;
     RECT  8.104 27.408 9.169 27.96 ;
     RECT  8.597 4.416 9.173 7.032 ;
     RECT  9.169 27.408 9.209 28.632 ;
     RECT  8.489 31.488 9.209 32.328 ;
     RECT  9.109 23.04 9.245 24.504 ;
     RECT  9.205 0.576 9.289 0.6 ;
     RECT  9.097 17.136 9.356 18.168 ;
     RECT  8.104 26.208 9.385 26.424 ;
     RECT  9.133 10.08 9.425 12.84 ;
     RECT  8.489 33.36 9.529 33.384 ;
     RECT  8.201 35.424 9.529 35.448 ;
     RECT  9.209 27.888 9.541 28.632 ;
     RECT  8.243 29.76 9.541 29.784 ;
     RECT  9.565 7.68 9.601 7.704 ;
     RECT  9.385 25.728 9.601 26.424 ;
     RECT  9.541 27.888 9.637 29.784 ;
     RECT  9.637 27.888 9.709 30.456 ;
     RECT  9.209 31.488 9.709 32.184 ;
     RECT  9.529 33.36 9.733 33.672 ;
     RECT  9.529 35.328 9.733 35.448 ;
     RECT  9.601 25.584 9.745 26.424 ;
     RECT  9.245 23.088 9.781 24.504 ;
     RECT  9.745 25.584 9.781 26.856 ;
     RECT  8.915 16.08 10.141 16.104 ;
     RECT  9.356 17.088 10.141 18.168 ;
     RECT  9.173 4.416 10.177 6.696 ;
     RECT  9.601 7.68 10.177 7.944 ;
     RECT  10.141 9.072 10.177 9.096 ;
     RECT  9.425 10.08 10.177 11.256 ;
     RECT  10.177 4.416 10.241 7.944 ;
     RECT  10.177 9.072 10.241 11.256 ;
     RECT  9.101 21.12 10.249 21.672 ;
     RECT  9.781 23.088 10.249 26.856 ;
     RECT  9.493 3.36 10.357 3.384 ;
     RECT  10.241 4.416 10.357 11.256 ;
     RECT  9.425 12.576 10.357 12.84 ;
     RECT  8.915 13.92 10.357 15 ;
     RECT  10.141 16.08 10.357 18.168 ;
     RECT  8.813 19.248 10.357 19.848 ;
     RECT  10.357 3.36 10.508 11.256 ;
     RECT  10.357 12.576 10.508 15 ;
     RECT  10.357 16.08 10.508 19.848 ;
     RECT  10.249 20.976 10.508 26.856 ;
     RECT  9.709 27.888 10.508 32.184 ;
     RECT  9.733 33.36 10.508 35.448 ;
     RECT  10.508 2.148 10.612 35.652 ;
     RECT  10.612 2.418 10.804 35.382 ;
     RECT  10.804 9.072 10.901 9.096 ;
     RECT  10.804 23.328 10.937 27.912 ;
     RECT  10.937 23.328 10.973 23.976 ;
     RECT  10.804 13.92 11.075 13.944 ;
     RECT  10.804 15.648 11.477 16.392 ;
     RECT  10.804 30.432 11.477 34.92 ;
     RECT  11.477 30.432 11.585 31.512 ;
     RECT  11.585 31.488 11.621 31.512 ;
     RECT  11.477 33.024 11.621 34.92 ;
     RECT  11.477 15.744 11.869 16.392 ;
     RECT  11.869 15.744 11.941 16.536 ;
     RECT  10.804 17.616 11.941 19.944 ;
     RECT  10.973 23.328 11.941 23.928 ;
     RECT  10.937 25.104 11.941 27.912 ;
     RECT  11.941 23.328 11.977 27.912 ;
     RECT  11.621 33.84 12.017 34.92 ;
     RECT  10.804 4.416 12.089 7.944 ;
     RECT  12.049 14.592 12.092 14.616 ;
     RECT  12.017 33.888 12.125 34.92 ;
     RECT  12.092 14.4 12.133 14.616 ;
     RECT  10.804 10.176 12.157 10.2 ;
     RECT  10.804 11.184 12.157 11.688 ;
     RECT  11.941 15.744 12.157 19.944 ;
     RECT  10.804 20.976 12.157 21.912 ;
     RECT  11.977 23.328 12.161 27.96 ;
     RECT  11.585 30.432 12.197 30.456 ;
     RECT  12.157 15.744 12.229 21.912 ;
     RECT  12.161 23.328 12.229 27.912 ;
     RECT  10.804 3.36 12.301 3.384 ;
     RECT  12.089 4.416 12.301 6.6 ;
     RECT  12.133 14.4 12.325 14.712 ;
     RECT  12.157 10.176 12.445 11.688 ;
     RECT  12.445 10.128 12.553 11.688 ;
     RECT  10.804 29.328 12.625 29.352 ;
     RECT  12.553 10.032 12.805 11.688 ;
     RECT  10.804 12.864 12.805 12.888 ;
     RECT  12.325 13.92 12.805 14.712 ;
     RECT  12.877 32.208 12.913 32.616 ;
     RECT  12.805 10.032 12.985 14.712 ;
     RECT  12.125 33.936 12.985 34.92 ;
     RECT  12.985 9.888 13.201 14.712 ;
     RECT  12.229 15.744 13.201 27.912 ;
     RECT  12.301 3.36 13.208 6.6 ;
     RECT  12.089 7.68 13.208 7.944 ;
     RECT  13.201 9.888 13.208 27.912 ;
     RECT  12.625 29.328 13.208 30.168 ;
     RECT  12.913 31.92 13.208 32.616 ;
     RECT  12.985 33.936 13.208 35.304 ;
     RECT  13.208 2.148 13.312 35.652 ;
     RECT  13.312 2.418 13.504 35.382 ;
     RECT  13.504 31.92 13.601 32.856 ;
     RECT  13.504 30.768 13.715 30.792 ;
     RECT  13.504 24.624 13.781 29.688 ;
     RECT  13.781 24.624 13.817 26.904 ;
     RECT  13.781 27.888 14.069 29.688 ;
     RECT  13.601 32.208 14.069 32.856 ;
     RECT  13.504 2.832 14.284 3.624 ;
     RECT  14.069 27.984 14.321 29.688 ;
     RECT  14.321 28.464 14.429 29.688 ;
     RECT  14.069 32.256 14.429 32.856 ;
     RECT  13.504 9.696 14.605 12.888 ;
     RECT  14.605 9.456 14.677 12.888 ;
     RECT  13.504 34.32 14.681 35.304 ;
     RECT  13.504 23.088 14.929 23.64 ;
     RECT  13.817 24.672 14.929 26.904 ;
     RECT  14.681 34.32 14.929 35.208 ;
     RECT  14.429 28.944 15.001 29.688 ;
     RECT  13.504 14.64 15.073 22.056 ;
     RECT  14.929 23.088 15.073 26.904 ;
     RECT  14.929 34.08 15.109 35.208 ;
     RECT  15.109 33.936 15.145 35.208 ;
     RECT  13.504 4.608 15.157 8.184 ;
     RECT  14.677 9.456 15.157 13.176 ;
     RECT  14.284 3.6 15.181 3.624 ;
     RECT  15.157 4.608 15.181 13.176 ;
     RECT  15.181 3.6 15.301 13.176 ;
     RECT  15.301 3.504 15.361 13.176 ;
     RECT  15.361 3.408 15.397 13.176 ;
     RECT  15.073 14.64 15.397 26.904 ;
     RECT  15.397 3.408 15.445 26.904 ;
     RECT  15.001 28.944 15.577 30.312 ;
     RECT  15.445 2.88 15.781 26.904 ;
     RECT  15.781 2.88 15.908 27.192 ;
     RECT  15.577 28.752 15.908 30.312 ;
     RECT  14.429 32.304 15.908 32.856 ;
     RECT  15.145 33.84 15.908 35.208 ;
     RECT  15.908 2.148 16.012 35.652 ;
     RECT  16.012 2.4 16.204 35.382 ;
     RECT  16.204 9.36 16.769 33.864 ;
     RECT  16.204 35.184 16.905 35.208 ;
     RECT  16.204 2.4 17.089 8.28 ;
     RECT  17.089 2.352 17.516 8.28 ;
     RECT  16.769 9.36 17.516 33.144 ;
     RECT  17.233 34.176 17.557 34.2 ;
     RECT  17.516 2.352 18.608 33.144 ;
     RECT  17.557 34.176 18.608 34.392 ;
     RECT  18.608 2.148 18.712 35.652 ;
     RECT  18.712 2.352 18.904 35.382 ;
     RECT  18.904 30.72 19.091 34.776 ;
     RECT  18.904 9.264 19.181 29.592 ;
     RECT  19.091 30.72 19.181 32.856 ;
     RECT  19.181 30.72 19.253 32.76 ;
     RECT  18.904 2.352 19.469 7.992 ;
     RECT  19.091 34.08 19.829 34.776 ;
     RECT  19.181 20.64 20.077 29.592 ;
     RECT  19.253 30.72 20.077 32.232 ;
     RECT  19.829 34.416 20.189 34.776 ;
     RECT  19.469 2.352 20.225 3.96 ;
     RECT  19.181 9.264 20.333 19.56 ;
     RECT  19.469 5.472 20.533 7.992 ;
     RECT  20.333 9.264 20.533 13.032 ;
     RECT  20.077 20.64 20.581 32.232 ;
     RECT  20.333 14.016 21.013 19.56 ;
     RECT  20.225 2.352 21.308 2.856 ;
     RECT  20.225 3.888 21.308 3.912 ;
     RECT  20.533 5.472 21.308 13.032 ;
     RECT  21.013 14.016 21.308 19.608 ;
     RECT  20.581 20.64 21.308 32.76 ;
     RECT  20.189 34.752 21.308 34.776 ;
     RECT  21.308 2.148 21.412 35.652 ;
     RECT  21.412 2.352 21.604 35.382 ;
     RECT  21.604 2.352 21.701 2.856 ;
     RECT  21.604 25.296 21.701 27.96 ;
     RECT  21.604 32.496 21.731 34.248 ;
     RECT  21.701 2.352 21.773 2.808 ;
     RECT  21.701 25.296 21.773 27.912 ;
     RECT  21.731 34.224 21.773 34.248 ;
     RECT  21.604 5.76 21.809 7.368 ;
     RECT  21.604 9.072 21.809 11.4 ;
     RECT  21.604 14.064 21.845 15.48 ;
     RECT  21.604 21.12 21.845 21.72 ;
     RECT  21.604 23.04 21.845 24.168 ;
     RECT  21.773 26.592 21.845 27.912 ;
     RECT  21.604 30.912 21.845 31.128 ;
     RECT  21.809 9.072 21.881 9.912 ;
     RECT  21.809 7.344 21.917 7.368 ;
     RECT  21.845 23.136 21.917 24.168 ;
     RECT  21.809 5.76 21.953 5.784 ;
     RECT  21.917 23.136 21.953 23.304 ;
     RECT  21.881 9.072 21.989 9.624 ;
     RECT  21.845 21.696 21.989 21.72 ;
     RECT  21.953 23.28 21.989 23.304 ;
     RECT  21.773 25.296 21.989 25.32 ;
     RECT  21.845 27.36 22.277 27.912 ;
     RECT  21.731 32.736 22.277 32.76 ;
     RECT  21.989 9.072 22.313 9.096 ;
     RECT  22.277 27.6 22.421 27.912 ;
     RECT  21.845 30.912 22.421 30.936 ;
     RECT  22.421 27.888 22.457 27.912 ;
     RECT  21.604 16.656 22.777 19.8 ;
     RECT  21.845 14.064 22.849 14.184 ;
     RECT  22.777 16.656 22.849 20.04 ;
     RECT  21.809 10.992 22.853 11.4 ;
     RECT  22.853 11.28 23.821 11.4 ;
     RECT  23.821 11.28 24.001 11.544 ;
     RECT  24.001 11.136 24.008 11.544 ;
     RECT  22.849 13.776 24.008 14.184 ;
     RECT  22.849 16.224 24.008 20.04 ;
     RECT  23.857 21.12 24.008 21.144 ;
     RECT  22.777 25.824 24.008 25.848 ;
     RECT  23.785 27.36 24.008 27.384 ;
     RECT  24.008 2.148 24.112 35.652 ;
     RECT  24.112 2.16 24.304 35.382 ;
     RECT  24.304 28.944 24.689 28.968 ;
     RECT  24.304 31.92 24.707 31.944 ;
     RECT  24.304 30.768 24.755 30.792 ;
     RECT  24.361 0.72 25.045 0.744 ;
     RECT  24.304 24.768 25.333 27.384 ;
     RECT  24.304 7.2 25.441 7.8 ;
     RECT  24.304 5.904 25.477 5.928 ;
     RECT  25.441 7.2 25.477 8.52 ;
     RECT  25.333 24.192 25.513 27.384 ;
     RECT  24.304 2.16 25.549 2.328 ;
     RECT  25.513 24.192 25.549 27.816 ;
     RECT  25.549 2.016 25.585 2.328 ;
     RECT  25.045 0.72 25.621 0.888 ;
     RECT  25.585 1.872 25.621 2.328 ;
     RECT  25.477 5.904 25.621 8.52 ;
     RECT  24.304 9.504 25.621 12.408 ;
     RECT  24.304 15.408 25.621 19.896 ;
     RECT  25.549 24.192 25.621 27.96 ;
     RECT  25.621 5.472 25.657 12.408 ;
     RECT  24.304 13.392 25.657 14.424 ;
     RECT  25.621 15.408 25.657 20.328 ;
     RECT  24.304 21.456 25.657 22.632 ;
     RECT  25.621 24.192 26.017 28.104 ;
     RECT  25.657 5.472 26.161 14.424 ;
     RECT  25.657 15.408 26.161 22.632 ;
     RECT  26.161 5.472 26.197 22.632 ;
     RECT  26.017 24.048 26.197 28.104 ;
     RECT  26.197 24.048 26.233 28.248 ;
     RECT  26.197 5.328 26.269 22.632 ;
     RECT  26.233 23.76 26.269 28.248 ;
     RECT  25.621 0.72 26.916 0.744 ;
     RECT  25.621 0.744 26.94 0.864 ;
     RECT  25.621 0.864 26.916 0.888 ;
     RECT  25.621 0.888 26.94 1.008 ;
     RECT  25.621 1.008 26.916 1.032 ;
     RECT  25.621 1.032 26.94 1.152 ;
     RECT  25.621 1.152 26.916 1.176 ;
     RECT  25.621 1.176 26.94 1.296 ;
     RECT  25.621 1.296 26.916 1.32 ;
     RECT  25.621 1.32 26.94 1.44 ;
     RECT  25.621 1.44 26.916 1.464 ;
     RECT  25.621 1.464 26.94 1.584 ;
     RECT  25.621 1.584 26.916 1.608 ;
     RECT  25.621 1.608 26.94 1.728 ;
     RECT  25.621 1.728 26.916 1.752 ;
     RECT  25.621 1.752 26.94 1.872 ;
     RECT  25.621 1.872 26.916 1.896 ;
     RECT  25.621 1.896 26.94 2.016 ;
     RECT  25.621 2.016 26.916 2.04 ;
     RECT  25.621 2.04 26.94 2.16 ;
     RECT  25.621 2.16 26.916 2.184 ;
     RECT  25.621 2.184 26.94 2.304 ;
     RECT  25.621 2.304 26.916 2.328 ;
     RECT  26.269 5.328 26.916 5.352 ;
     RECT  26.269 5.352 26.94 5.472 ;
     RECT  26.269 5.472 26.916 5.496 ;
     RECT  26.269 5.496 26.94 5.616 ;
     RECT  26.269 5.616 26.916 5.64 ;
     RECT  26.269 5.64 26.94 5.76 ;
     RECT  26.269 5.76 26.916 5.784 ;
     RECT  26.269 5.784 26.94 5.904 ;
     RECT  26.269 5.904 26.916 5.928 ;
     RECT  26.269 5.928 26.94 6.048 ;
     RECT  26.269 6.048 26.916 6.072 ;
     RECT  26.269 6.072 26.94 6.192 ;
     RECT  26.269 6.192 26.916 6.216 ;
     RECT  26.269 6.216 26.94 6.336 ;
     RECT  26.269 6.336 26.916 6.36 ;
     RECT  26.269 6.36 26.94 6.48 ;
     RECT  26.269 6.48 26.916 6.504 ;
     RECT  26.269 6.504 26.94 6.624 ;
     RECT  26.269 6.624 26.916 6.648 ;
     RECT  26.269 6.648 26.94 6.768 ;
     RECT  26.269 6.768 26.916 6.792 ;
     RECT  26.269 6.792 26.94 6.912 ;
     RECT  26.269 6.912 26.916 6.936 ;
     RECT  26.269 6.936 26.94 7.056 ;
     RECT  26.269 7.056 26.916 7.08 ;
     RECT  26.269 7.08 26.94 7.2 ;
     RECT  26.269 7.2 26.916 7.224 ;
     RECT  26.269 7.224 26.94 7.344 ;
     RECT  26.269 7.344 26.916 7.368 ;
     RECT  26.269 7.368 26.94 7.488 ;
     RECT  26.269 7.488 26.916 7.512 ;
     RECT  26.269 7.512 26.94 7.632 ;
     RECT  26.269 7.632 26.916 7.656 ;
     RECT  26.269 7.656 26.94 7.776 ;
     RECT  26.269 7.776 26.916 7.8 ;
     RECT  26.269 7.8 26.94 7.92 ;
     RECT  26.269 7.92 26.916 7.944 ;
     RECT  26.269 7.944 26.94 8.064 ;
     RECT  26.269 8.064 26.916 8.088 ;
     RECT  26.269 8.088 26.94 8.208 ;
     RECT  26.269 8.208 26.916 8.232 ;
     RECT  26.269 8.232 26.94 8.352 ;
     RECT  26.269 8.352 26.916 8.376 ;
     RECT  26.269 8.376 26.94 8.496 ;
     RECT  26.269 8.496 26.916 8.52 ;
     RECT  26.269 8.52 26.94 8.64 ;
     RECT  26.269 8.64 26.916 8.664 ;
     RECT  26.269 8.664 26.94 8.784 ;
     RECT  26.269 8.784 26.916 8.808 ;
     RECT  26.269 8.808 26.94 8.928 ;
     RECT  26.269 8.928 26.916 8.952 ;
     RECT  26.269 8.952 26.94 9.072 ;
     RECT  26.269 9.072 26.916 9.096 ;
     RECT  26.269 9.096 26.94 9.216 ;
     RECT  26.269 9.216 26.916 9.24 ;
     RECT  26.269 9.24 26.94 9.36 ;
     RECT  26.269 9.36 26.916 9.384 ;
     RECT  26.269 9.384 26.94 9.504 ;
     RECT  26.269 9.504 26.916 9.528 ;
     RECT  26.269 9.528 26.94 9.648 ;
     RECT  26.269 9.648 26.916 9.672 ;
     RECT  26.269 9.672 26.94 9.792 ;
     RECT  26.269 9.792 26.916 9.816 ;
     RECT  26.269 9.816 26.94 9.936 ;
     RECT  26.269 9.936 26.916 9.96 ;
     RECT  26.269 9.96 26.94 10.08 ;
     RECT  26.269 10.08 26.916 10.104 ;
     RECT  26.269 10.104 26.94 10.224 ;
     RECT  26.269 10.224 26.916 10.248 ;
     RECT  26.269 10.248 26.94 10.368 ;
     RECT  26.269 10.368 26.916 10.392 ;
     RECT  26.269 10.392 26.94 10.512 ;
     RECT  26.269 10.512 26.916 10.536 ;
     RECT  26.269 10.536 26.94 10.656 ;
     RECT  26.269 10.656 26.916 10.68 ;
     RECT  26.269 10.68 26.94 10.8 ;
     RECT  26.269 10.8 26.916 10.824 ;
     RECT  26.269 10.824 26.94 10.944 ;
     RECT  26.269 10.944 26.916 10.968 ;
     RECT  26.269 10.968 26.94 11.088 ;
     RECT  26.269 11.088 26.916 11.112 ;
     RECT  26.269 11.112 26.94 11.232 ;
     RECT  26.269 11.232 26.916 11.256 ;
     RECT  26.269 11.256 26.94 11.376 ;
     RECT  26.269 11.376 26.916 11.4 ;
     RECT  26.269 11.4 26.94 11.52 ;
     RECT  26.269 11.52 26.916 11.544 ;
     RECT  26.269 11.544 26.94 11.664 ;
     RECT  26.269 11.664 26.916 11.688 ;
     RECT  26.269 11.688 26.94 11.808 ;
     RECT  26.269 11.808 26.916 11.832 ;
     RECT  26.269 11.832 26.94 11.952 ;
     RECT  26.269 11.952 26.916 11.976 ;
     RECT  26.269 11.976 26.94 12.096 ;
     RECT  26.269 12.096 26.916 12.12 ;
     RECT  26.269 12.12 26.94 12.24 ;
     RECT  26.269 12.24 26.916 12.264 ;
     RECT  26.269 12.264 26.94 12.384 ;
     RECT  26.269 12.384 26.916 12.408 ;
     RECT  26.269 12.408 26.94 12.528 ;
     RECT  26.269 12.528 26.916 12.552 ;
     RECT  26.269 12.552 26.94 12.672 ;
     RECT  26.269 12.672 26.916 12.696 ;
     RECT  26.269 12.696 26.94 12.816 ;
     RECT  26.269 12.816 26.916 12.84 ;
     RECT  26.269 12.84 26.94 12.96 ;
     RECT  26.269 12.96 26.916 12.984 ;
     RECT  26.269 12.984 26.94 13.104 ;
     RECT  26.269 13.104 26.916 13.128 ;
     RECT  26.269 13.128 26.94 13.248 ;
     RECT  26.269 13.248 26.916 13.272 ;
     RECT  26.269 13.272 26.94 13.392 ;
     RECT  26.269 13.392 26.916 13.416 ;
     RECT  26.269 13.416 26.94 13.536 ;
     RECT  26.269 13.536 26.916 13.56 ;
     RECT  26.269 13.56 26.94 13.68 ;
     RECT  26.269 13.68 26.916 13.704 ;
     RECT  26.269 13.704 26.94 13.824 ;
     RECT  26.269 13.824 26.916 13.848 ;
     RECT  26.269 13.848 26.94 13.968 ;
     RECT  26.269 13.968 26.916 13.992 ;
     RECT  26.269 13.992 26.94 14.112 ;
     RECT  26.269 14.112 26.916 14.136 ;
     RECT  26.269 14.136 26.94 14.256 ;
     RECT  26.269 14.256 26.916 14.28 ;
     RECT  26.269 14.28 26.94 14.4 ;
     RECT  26.269 14.4 26.916 14.424 ;
     RECT  26.269 14.424 26.94 14.544 ;
     RECT  26.269 14.544 26.916 14.568 ;
     RECT  26.269 14.568 26.94 14.688 ;
     RECT  26.269 14.688 26.916 14.712 ;
     RECT  26.269 14.712 26.94 14.832 ;
     RECT  26.269 14.832 26.916 14.856 ;
     RECT  26.269 14.856 26.94 14.976 ;
     RECT  26.269 14.976 26.916 15 ;
     RECT  26.269 15 26.94 15.12 ;
     RECT  26.269 15.12 26.916 15.144 ;
     RECT  26.269 15.144 26.94 15.264 ;
     RECT  26.269 15.264 26.916 15.288 ;
     RECT  26.269 15.288 26.94 15.408 ;
     RECT  26.269 15.408 26.916 15.432 ;
     RECT  26.269 15.432 26.94 15.552 ;
     RECT  26.269 15.552 26.916 15.576 ;
     RECT  26.269 15.576 26.94 15.696 ;
     RECT  26.269 15.696 26.916 15.72 ;
     RECT  26.269 15.72 26.94 15.84 ;
     RECT  26.269 15.84 26.916 15.864 ;
     RECT  26.269 15.864 26.94 15.984 ;
     RECT  26.269 15.984 26.916 16.008 ;
     RECT  26.269 16.008 26.94 16.128 ;
     RECT  26.269 16.128 26.916 16.152 ;
     RECT  26.269 16.152 26.94 16.272 ;
     RECT  26.269 16.272 26.916 16.296 ;
     RECT  26.269 16.296 26.94 16.416 ;
     RECT  26.269 16.416 26.916 16.44 ;
     RECT  26.269 16.44 26.94 16.56 ;
     RECT  26.269 16.56 26.916 16.584 ;
     RECT  26.269 16.584 26.94 16.704 ;
     RECT  26.269 16.704 26.916 16.728 ;
     RECT  26.269 16.728 26.94 16.848 ;
     RECT  26.269 16.848 26.916 16.872 ;
     RECT  26.269 16.872 26.94 16.992 ;
     RECT  26.269 16.992 26.916 17.016 ;
     RECT  26.269 17.016 26.94 17.136 ;
     RECT  26.269 17.136 26.916 17.16 ;
     RECT  26.269 17.16 26.94 17.28 ;
     RECT  26.269 17.28 26.916 17.304 ;
     RECT  26.269 17.304 26.94 17.424 ;
     RECT  26.269 17.424 26.916 17.448 ;
     RECT  26.269 17.448 26.94 17.568 ;
     RECT  26.269 17.568 26.916 17.592 ;
     RECT  26.269 17.592 26.94 17.712 ;
     RECT  26.269 17.712 26.916 17.736 ;
     RECT  26.269 17.736 26.94 17.856 ;
     RECT  26.269 17.856 26.916 17.88 ;
     RECT  26.269 17.88 26.94 18 ;
     RECT  26.269 18 26.916 18.024 ;
     RECT  26.269 18.024 26.94 18.144 ;
     RECT  26.269 18.144 26.916 18.168 ;
     RECT  26.269 18.168 26.94 18.288 ;
     RECT  26.269 18.288 26.916 18.312 ;
     RECT  26.269 18.312 26.94 18.432 ;
     RECT  26.269 18.432 26.916 18.456 ;
     RECT  26.269 18.456 26.94 18.576 ;
     RECT  26.269 18.576 26.916 18.6 ;
     RECT  26.269 18.6 26.94 18.72 ;
     RECT  26.269 18.72 26.916 18.744 ;
     RECT  26.269 18.744 26.94 18.864 ;
     RECT  26.269 18.864 26.916 18.888 ;
     RECT  26.269 18.888 26.94 19.008 ;
     RECT  26.269 19.008 26.916 19.032 ;
     RECT  26.269 19.032 26.94 19.152 ;
     RECT  26.269 19.152 26.916 19.176 ;
     RECT  26.269 19.176 26.94 19.296 ;
     RECT  26.269 19.296 26.916 19.32 ;
     RECT  26.269 19.32 26.94 19.44 ;
     RECT  26.269 19.44 26.916 19.464 ;
     RECT  26.269 19.464 26.94 19.584 ;
     RECT  26.269 19.584 26.916 19.608 ;
     RECT  26.269 19.608 26.94 19.728 ;
     RECT  26.269 19.728 26.916 19.752 ;
     RECT  26.269 19.752 26.94 19.872 ;
     RECT  26.269 19.872 26.916 19.896 ;
     RECT  26.269 19.896 26.94 20.016 ;
     RECT  26.269 20.016 26.916 20.04 ;
     RECT  26.269 20.04 26.94 20.16 ;
     RECT  26.269 20.16 26.916 20.184 ;
     RECT  26.269 20.184 26.94 20.304 ;
     RECT  26.269 20.304 26.916 20.328 ;
     RECT  26.269 20.328 26.94 20.448 ;
     RECT  26.269 20.448 26.916 20.472 ;
     RECT  26.269 20.472 26.94 20.592 ;
     RECT  26.269 20.592 26.916 20.616 ;
     RECT  26.269 20.616 26.94 20.736 ;
     RECT  26.269 20.736 26.916 20.76 ;
     RECT  26.269 20.76 26.94 20.88 ;
     RECT  26.269 20.88 26.916 20.904 ;
     RECT  26.269 20.904 26.94 21.024 ;
     RECT  26.269 21.024 26.916 21.048 ;
     RECT  26.269 21.048 26.94 21.168 ;
     RECT  26.269 21.168 26.916 21.192 ;
     RECT  26.269 21.192 26.94 21.312 ;
     RECT  26.269 21.312 26.916 21.336 ;
     RECT  26.269 21.336 26.94 21.456 ;
     RECT  26.269 21.456 26.916 21.48 ;
     RECT  26.269 21.48 26.94 21.6 ;
     RECT  26.269 21.6 26.916 21.624 ;
     RECT  26.269 21.624 26.94 21.744 ;
     RECT  26.269 21.744 26.916 21.768 ;
     RECT  26.269 21.768 26.94 21.888 ;
     RECT  26.269 21.888 26.916 21.912 ;
     RECT  26.269 21.912 26.94 22.032 ;
     RECT  26.269 22.032 26.916 22.056 ;
     RECT  26.269 22.056 26.94 22.176 ;
     RECT  26.269 22.176 26.916 22.2 ;
     RECT  26.269 22.2 26.94 22.32 ;
     RECT  26.269 22.32 26.916 22.344 ;
     RECT  26.269 22.344 26.94 22.464 ;
     RECT  26.269 22.464 26.916 22.488 ;
     RECT  26.269 22.488 26.94 22.608 ;
     RECT  26.269 22.608 26.916 22.632 ;
     RECT  26.269 22.632 26.94 22.752 ;
     RECT  26.269 22.752 26.916 22.776 ;
     RECT  26.269 22.776 26.94 22.896 ;
     RECT  26.269 22.896 26.916 22.92 ;
     RECT  26.269 22.92 26.94 23.04 ;
     RECT  26.269 23.04 26.916 23.064 ;
     RECT  26.269 23.064 26.94 23.184 ;
     RECT  26.269 23.184 26.916 23.208 ;
     RECT  26.269 23.208 26.94 23.328 ;
     RECT  26.269 23.328 26.916 23.352 ;
     RECT  26.269 23.352 26.94 23.472 ;
     RECT  26.269 23.472 26.916 23.496 ;
     RECT  26.269 23.496 26.94 23.616 ;
     RECT  26.269 23.616 26.916 23.64 ;
     RECT  26.269 23.64 26.94 23.76 ;
     RECT  26.269 23.76 26.916 23.784 ;
     RECT  26.269 23.784 26.94 23.904 ;
     RECT  26.269 23.904 26.916 23.928 ;
     RECT  26.269 23.928 26.94 24.048 ;
     RECT  26.269 24.048 26.916 24.072 ;
     RECT  26.269 24.072 26.94 24.192 ;
     RECT  26.269 24.192 26.916 24.216 ;
     RECT  26.269 24.216 26.94 24.336 ;
     RECT  26.269 24.336 26.916 24.36 ;
     RECT  26.269 24.36 26.94 24.48 ;
     RECT  26.269 24.48 26.916 24.504 ;
     RECT  26.269 24.504 26.94 24.624 ;
     RECT  26.269 24.624 26.916 24.648 ;
     RECT  26.269 24.648 26.94 24.768 ;
     RECT  26.269 24.768 26.916 24.792 ;
     RECT  26.269 24.792 26.94 24.912 ;
     RECT  26.269 24.912 26.916 24.936 ;
     RECT  26.269 24.936 26.94 25.056 ;
     RECT  26.269 25.056 26.916 25.08 ;
     RECT  26.269 25.08 26.94 25.2 ;
     RECT  26.269 25.2 26.916 25.224 ;
     RECT  26.269 25.224 26.94 25.344 ;
     RECT  26.269 25.344 26.916 25.368 ;
     RECT  26.269 25.368 26.94 25.488 ;
     RECT  26.269 25.488 26.916 25.512 ;
     RECT  26.269 25.512 26.94 25.632 ;
     RECT  26.269 25.632 26.916 25.656 ;
     RECT  26.269 25.656 26.94 25.776 ;
     RECT  26.269 25.776 26.916 25.8 ;
     RECT  26.269 25.8 26.94 25.92 ;
     RECT  26.269 25.92 26.916 25.944 ;
     RECT  26.269 25.944 26.94 26.064 ;
     RECT  26.269 26.064 26.916 26.088 ;
     RECT  26.269 26.088 26.94 26.208 ;
     RECT  26.269 26.208 26.916 26.232 ;
     RECT  26.269 26.232 26.94 26.352 ;
     RECT  26.269 26.352 26.916 26.376 ;
     RECT  26.269 26.376 26.94 26.496 ;
     RECT  26.269 26.496 26.916 26.52 ;
     RECT  26.269 26.52 26.94 26.64 ;
     RECT  26.269 26.64 26.916 26.664 ;
     RECT  26.269 26.664 26.94 26.784 ;
     RECT  26.269 26.784 26.916 26.808 ;
     RECT  26.269 26.808 26.94 26.928 ;
     RECT  26.269 26.928 26.916 26.952 ;
     RECT  26.269 26.952 26.94 27.072 ;
     RECT  26.269 27.072 26.916 27.096 ;
     RECT  26.269 27.096 26.94 27.216 ;
     RECT  26.269 27.216 26.916 27.24 ;
     RECT  26.269 27.24 26.94 27.36 ;
     RECT  26.269 27.36 26.916 27.384 ;
     RECT  26.269 27.384 26.94 27.504 ;
     RECT  26.269 27.504 26.916 27.528 ;
     RECT  26.269 27.528 26.94 27.648 ;
     RECT  26.269 27.648 26.916 27.672 ;
     RECT  26.269 27.672 26.94 27.792 ;
     RECT  26.269 27.792 26.916 27.816 ;
     RECT  26.269 27.816 26.94 27.936 ;
     RECT  26.269 27.936 26.916 27.96 ;
     RECT  26.269 27.96 26.94 28.08 ;
     RECT  26.269 28.08 26.916 28.104 ;
     RECT  26.269 28.104 26.94 28.224 ;
     RECT  26.269 28.224 26.916 28.248 ;
    LAYER M5 ;
     RECT  9.096 0.016 9.216 0.084 ;
     RECT  9.072 0.084 9.24 0.611 ;
     RECT  2.4 2.137 2.52 2.151 ;
     RECT  5.1 2.137 5.22 2.151 ;
     RECT  7.8 2.137 7.92 2.151 ;
     RECT  9.072 0.611 9.096 2.151 ;
     RECT  10.5 2.137 10.62 2.151 ;
     RECT  13.2 2.137 13.32 2.151 ;
     RECT  15.9 2.137 16.02 2.151 ;
     RECT  18.6 2.137 18.72 2.151 ;
     RECT  21.3 2.137 21.42 2.151 ;
     RECT  24 2.137 24.12 2.151 ;
     RECT  13.2 2.151 13.512 2.821 ;
     RECT  15.9 2.151 16.212 2.869 ;
     RECT  10.5 2.151 10.812 3.349 ;
     RECT  15.456 2.869 16.212 3.493 ;
     RECT  13.2 2.821 14.232 3.635 ;
     RECT  15.312 3.493 16.212 3.635 ;
     RECT  15.9 3.635 16.212 3.877 ;
     RECT  7.8 2.151 9.096 3.925 ;
     RECT  10.368 3.349 10.812 4.405 ;
     RECT  7.488 3.925 9.096 5.029 ;
     RECT  15.9 3.877 17.016 5.219 ;
     RECT  0.144 5.461 0.168 5.603 ;
     RECT  7.392 5.029 9.096 5.987 ;
     RECT  18.6 2.151 18.912 7.093 ;
     RECT  15.9 5.219 16.212 7.909 ;
     RECT  10.368 4.405 11.544 8.485 ;
     RECT  18.6 7.093 19.896 8.485 ;
     RECT  21.3 2.151 21.612 8.485 ;
     RECT  15.168 7.909 16.212 8.771 ;
     RECT  17.568 6.805 17.592 9.347 ;
     RECT  10.272 8.485 11.544 9.923 ;
     RECT  13.2 3.635 13.512 10.021 ;
     RECT  18.6 8.485 21.612 10.067 ;
     RECT  15.9 8.771 16.212 10.357 ;
     RECT  15.504 10.357 16.872 10.835 ;
     RECT  7.488 5.987 9.096 10.933 ;
     RECT  6.912 10.933 9.096 11.267 ;
     RECT  15.504 10.835 16.212 11.797 ;
     RECT  5.1 2.151 5.412 11.941 ;
     RECT  15.072 11.797 16.212 12.421 ;
     RECT  17.472 11.941 17.496 12.421 ;
     RECT  7.488 11.267 9.096 12.805 ;
     RECT  10.5 9.923 11.544 12.805 ;
     RECT  15.072 12.421 17.496 13.139 ;
     RECT  15.072 13.139 16.212 13.141 ;
     RECT  18.6 10.067 19.896 13.621 ;
     RECT  5.1 11.941 5.544 13.907 ;
     RECT  7.488 12.805 11.544 13.909 ;
     RECT  12.672 10.021 13.512 13.909 ;
     RECT  17.856 13.621 19.896 14.627 ;
     RECT  14.688 13.141 16.212 14.675 ;
     RECT  6.912 13.909 13.512 15.827 ;
     RECT  6.912 15.827 11.544 16.499 ;
     RECT  12.672 15.827 13.512 16.547 ;
     RECT  15.648 14.675 16.212 16.981 ;
     RECT  18.6 14.627 19.896 17.029 ;
     RECT  15.648 16.981 17.064 17.123 ;
     RECT  7.488 16.499 11.544 17.651 ;
     RECT  15.648 17.123 16.212 18.565 ;
     RECT  18.24 17.029 19.896 18.707 ;
     RECT  18.6 18.707 19.896 18.851 ;
     RECT  7.8 17.651 11.544 18.947 ;
     RECT  5.1 13.907 5.412 19.093 ;
     RECT  15.408 18.565 16.212 19.237 ;
     RECT  15.408 19.237 17.16 19.427 ;
     RECT  7.8 18.947 10.812 19.619 ;
     RECT  11.856 19.093 11.88 19.861 ;
     RECT  12.912 16.547 13.512 19.861 ;
     RECT  15.456 19.427 17.16 20.003 ;
     RECT  5.1 19.093 6.216 20.053 ;
     RECT  7.8 19.619 8.328 20.099 ;
     RECT  5.1 20.053 6.456 20.485 ;
     RECT  4.992 20.485 6.456 20.963 ;
     RECT  11.856 19.861 13.512 21.155 ;
     RECT  15.456 20.003 16.212 21.347 ;
     RECT  4.992 20.963 6.216 21.395 ;
     RECT  7.8 20.099 8.112 21.637 ;
     RECT  15.9 21.347 16.212 21.973 ;
     RECT  17.424 21.637 17.448 21.973 ;
     RECT  18.6 18.851 19.464 22.259 ;
     RECT  15.9 21.973 17.448 22.499 ;
     RECT  12.816 21.155 13.512 22.741 ;
     RECT  10.032 19.619 10.812 23.029 ;
     RECT  9.12 23.029 10.812 23.171 ;
     RECT  7.392 21.637 8.112 23.315 ;
     RECT  15.9 22.499 16.536 23.315 ;
     RECT  12.24 22.741 13.512 23.363 ;
     RECT  15.9 23.315 16.212 24.133 ;
     RECT  17.376 23.557 17.4 24.563 ;
     RECT  4.992 21.395 6.168 24.805 ;
     RECT  2.4 2.151 2.712 25.045 ;
     RECT  24 2.151 24.312 25.045 ;
     RECT  18.6 22.259 18.912 25.093 ;
     RECT  18.6 25.093 19.08 25.235 ;
     RECT  9.936 23.171 10.812 25.333 ;
     RECT  9.936 25.333 11.064 25.571 ;
     RECT  20.304 24.469 20.328 26.099 ;
     RECT  2.4 25.045 3.384 26.915 ;
     RECT  15.792 24.133 16.212 27.203 ;
     RECT  4.992 24.805 6.216 27.205 ;
     RECT  21.3 10.067 21.612 28.453 ;
     RECT  4.992 27.205 6.312 28.643 ;
     RECT  20.976 28.453 21.612 28.885 ;
     RECT  7.8 23.315 8.112 29.029 ;
     RECT  18.6 25.235 18.912 29.077 ;
     RECT  20.928 28.885 21.612 29.171 ;
     RECT  15.9 27.203 16.212 29.221 ;
     RECT  17.664 29.077 18.912 29.221 ;
     RECT  9.936 25.571 10.812 29.317 ;
     RECT  12.576 23.363 13.512 29.363 ;
     RECT  15.9 29.221 19.032 29.411 ;
     RECT  13.2 29.363 13.512 29.605 ;
     RECT  4.992 28.643 5.64 29.795 ;
     RECT  20.976 29.171 21.612 29.795 ;
     RECT  15.9 29.411 18.912 30.515 ;
     RECT  7.8 29.029 8.232 30.611 ;
     RECT  9.552 29.317 10.812 30.709 ;
     RECT  24 25.045 24.744 30.803 ;
     RECT  21.168 29.795 21.612 31.093 ;
     RECT  7.8 30.611 8.112 31.285 ;
     RECT  5.1 29.795 5.64 31.379 ;
     RECT  18.336 30.515 18.912 31.523 ;
     RECT  21.12 31.093 21.612 31.955 ;
     RECT  24 30.803 24.696 31.955 ;
     RECT  7.68 31.285 8.112 32.149 ;
     RECT  21.3 31.955 21.612 32.485 ;
     RECT  13.2 29.605 13.704 32.531 ;
     RECT  9.552 30.709 11.4 33.059 ;
     RECT  15.9 30.515 17.064 33.107 ;
     RECT  18.6 31.523 18.912 33.109 ;
     RECT  15.9 33.107 16.968 33.155 ;
     RECT  7.44 32.149 8.112 33.251 ;
     RECT  9.552 33.059 10.92 33.683 ;
     RECT  21.3 32.485 21.72 34.259 ;
     RECT  18.6 33.109 19.08 34.453 ;
     RECT  9.744 33.683 10.812 34.643 ;
     RECT  18.6 34.453 19.368 34.787 ;
     RECT  15.9 33.155 16.872 35.219 ;
     RECT  2.4 26.915 2.712 35.649 ;
     RECT  5.1 31.379 5.412 35.649 ;
     RECT  7.8 33.251 8.112 35.649 ;
     RECT  10.5 34.643 10.812 35.649 ;
     RECT  13.2 32.531 13.512 35.649 ;
     RECT  15.9 35.219 16.212 35.649 ;
     RECT  18.6 34.787 18.912 35.649 ;
     RECT  21.3 34.259 21.612 35.649 ;
     RECT  24 31.955 24.312 35.649 ;
     RECT  2.4 35.649 2.52 35.663 ;
     RECT  5.1 35.649 5.22 35.663 ;
     RECT  7.8 35.649 7.92 35.663 ;
     RECT  10.5 35.649 10.62 35.663 ;
     RECT  13.2 35.649 13.32 35.663 ;
     RECT  15.9 35.649 16.02 35.663 ;
     RECT  18.6 35.649 18.72 35.663 ;
     RECT  21.3 35.649 21.42 35.663 ;
     RECT  24 35.649 24.12 35.663 ;
     RECT  9.096 0.611 9.24 2.137 ;
     RECT  7.92 2.137 9.072 2.151 ;
     RECT  9.096 2.137 10.5 3.349 ;
     RECT  14.232 2.869 15.456 3.493 ;
     RECT  9.096 3.349 10.368 8.485 ;
     RECT  14.232 3.493 15.312 3.635 ;
     RECT  16.212 6.805 17.568 9.347 ;
     RECT  17.592 6.805 18.6 9.347 ;
     RECT  19.896 7.093 21.3 8.485 ;
     RECT  9.096 8.485 10.272 9.923 ;
     RECT  16.212 9.347 16.872 10.357 ;
     RECT  9.096 9.923 10.5 12.805 ;
     RECT  11.544 10.021 12.672 13.909 ;
     RECT  19.896 10.067 21.3 18.851 ;
     RECT  16.212 10.835 16.872 11.941 ;
     RECT  5.412 10.933 6.912 11.267 ;
     RECT  5.412 11.267 5.544 11.941 ;
     RECT  16.212 11.941 17.472 12.421 ;
     RECT  17.496 11.941 18.6 13.139 ;
     RECT  17.856 13.139 18.6 13.621 ;
     RECT  13.512 13.141 14.688 14.675 ;
     RECT  5.412 13.907 5.544 13.909 ;
     RECT  5.412 13.909 6.912 16.499 ;
     RECT  11.544 15.827 12.672 16.547 ;
     RECT  11.544 16.547 12.912 18.947 ;
     RECT  17.064 17.029 18.24 17.123 ;
     RECT  18.24 18.707 18.6 19.237 ;
     RECT  10.812 18.947 12.912 19.093 ;
     RECT  10.812 19.093 11.856 21.155 ;
     RECT  11.88 19.093 12.912 19.861 ;
     RECT  17.16 19.237 18.6 20.003 ;
     RECT  6.456 20.053 7.8 20.963 ;
     RECT  6.216 20.963 7.8 21.395 ;
     RECT  6.168 21.395 7.8 21.637 ;
     RECT  6.168 21.637 7.392 23.315 ;
     RECT  16.212 21.637 17.424 21.973 ;
     RECT  17.448 21.637 18.6 22.499 ;
     RECT  16.536 22.499 18.6 23.315 ;
     RECT  10.812 22.741 12.24 23.363 ;
     RECT  8.112 23.029 9.12 23.171 ;
     RECT  6.168 23.315 6.216 24.805 ;
     RECT  16.212 23.315 18.6 23.557 ;
     RECT  16.212 23.557 17.376 24.563 ;
     RECT  17.4 23.557 18.6 24.563 ;
     RECT  18.912 24.469 20.304 25.093 ;
     RECT  20.328 24.469 21.3 26.099 ;
     RECT  19.08 25.093 20.304 25.235 ;
     RECT  18.912 25.235 20.304 26.099 ;
     RECT  11.064 25.333 12.576 25.571 ;
     RECT  6.312 27.205 7.8 28.643 ;
     RECT  16.212 29.077 17.664 29.221 ;
     RECT  8.232 29.317 9.552 30.611 ;
     RECT  21.12 29.795 21.168 31.093 ;
     RECT  17.064 30.515 18.336 31.523 ;
     RECT  8.112 30.611 9.552 33.683 ;
  END
END qkd_static_kv_layer_programme_img
END LIBRARY
